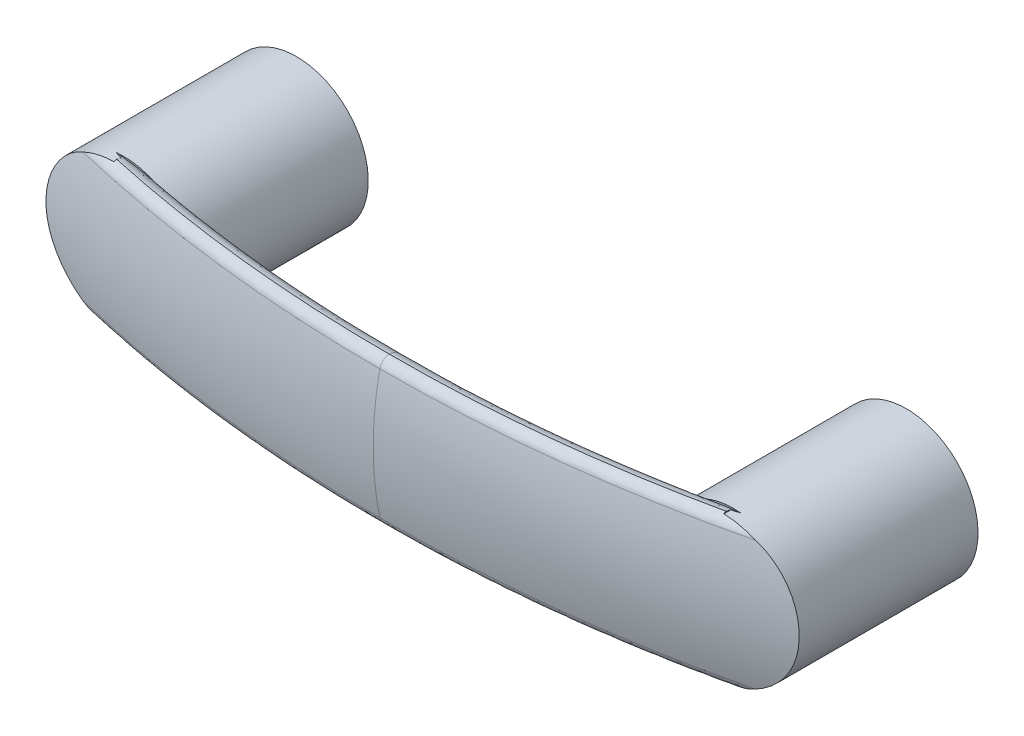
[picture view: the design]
ISO-10303-21;
HEADER;
FILE_DESCRIPTION(('STEP AP214'),'2;1');
FILE_NAME('part.step','',(''),(''),'','','');
FILE_SCHEMA(('AUTOMOTIVE_DESIGN { 1 0 10303 214 1 1 1 1 }'));
ENDSEC;
DATA;
#1=APPLICATION_CONTEXT('core data for automotive mechanical design processes');
#2=APPLICATION_PROTOCOL_DEFINITION('international standard','automotive_design',2000,#1);
#3=PRODUCT_CONTEXT('',#1,'mechanical');
#4=PRODUCT('Part','Part','',(#3));
#5=PRODUCT_RELATED_PRODUCT_CATEGORY('part','',(#4));
#6=PRODUCT_DEFINITION_FORMATION('','',#4);
#7=PRODUCT_DEFINITION_CONTEXT('part definition',#1,'design');
#8=PRODUCT_DEFINITION('design','',#6,#7);
#9=PRODUCT_DEFINITION_SHAPE('','',#8);
#10=(LENGTH_UNIT() NAMED_UNIT(*) SI_UNIT(.MILLI.,.METRE.));
#11=(NAMED_UNIT(*) PLANE_ANGLE_UNIT() SI_UNIT($,.RADIAN.));
#12=(NAMED_UNIT(*) SI_UNIT($,.STERADIAN.) SOLID_ANGLE_UNIT());
#13=UNCERTAINTY_MEASURE_WITH_UNIT(LENGTH_MEASURE(1.E-05),#10,'distance_accuracy_value','');
#14=(GEOMETRIC_REPRESENTATION_CONTEXT(3) GLOBAL_UNCERTAINTY_ASSIGNED_CONTEXT((#13)) GLOBAL_UNIT_ASSIGNED_CONTEXT((#10,
#11,#12)) REPRESENTATION_CONTEXT('',''));
#15=CARTESIAN_POINT('',(0.,0.,0.));
#16=DIRECTION('',(0.,0.,1.));
#17=DIRECTION('',(1.,0.,0.));
#18=AXIS2_PLACEMENT_3D('',#15,#16,#17);
#19=CARTESIAN_POINT('',(125.191834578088,0.,31.4954607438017));
#20=DIRECTION('',(0.940144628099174,0.,-0.340775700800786));
#21=DIRECTION('',(0.,1.,0.));
#22=AXIS2_PLACEMENT_3D('',#19,#20,#21);
#23=CIRCLE('',#22,17.6);
#24=CARTESIAN_POINT('',(47.2434292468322,0.,-184.999446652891));
#25=DIRECTION('',(0.,-1.,0.));
#26=AXIS1_PLACEMENT('',#24,#25);
#27=SURFACE_OF_REVOLUTION('',#23,#26);
#28=CARTESIAN_POINT('',(47.2434292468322,9.54893617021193,-184.999446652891));
#29=DIRECTION('',(0.,-1.,0.));
#30=DIRECTION('',(1.,0.,0.));
#31=AXIS2_PLACEMENT_3D('',#28,#29,#30);
#32=CIRCLE('',#31,215.315634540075);
#33=CARTESIAN_POINT('',(88.0394306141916,9.54893617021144,26.4160417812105));
#34=VERTEX_POINT('',#33);
#35=CARTESIAN_POINT('',(46.75,9.54893617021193,30.3156225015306));
#36=VERTEX_POINT('',#35);
#37=EDGE_CURVE('E344',#34,#36,#32,.T.);
#38=ORIENTED_EDGE('',*,*,#37,.F.);
#39=CARTESIAN_POINT('',(88.0394306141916,9.54893617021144,26.4160417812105));
#40=CARTESIAN_POINT('',(87.7659781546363,9.39256816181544,26.3659144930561));
#41=CARTESIAN_POINT('',(87.5001444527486,9.22495922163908,26.3100965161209));
#42=CARTESIAN_POINT('',(86.9850934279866,8.86870622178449,26.1903628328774));
#43=CARTESIAN_POINT('',(86.7358674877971,8.68007320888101,26.1264513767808));
#44=CARTESIAN_POINT('',(86.2549146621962,8.28288099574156,25.9936978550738));
#45=CARTESIAN_POINT('',(86.0232030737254,8.07430472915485,25.9248515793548));
#46=CARTESIAN_POINT('',(85.5785573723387,7.63856320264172,25.7851894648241));
#47=CARTESIAN_POINT('',(85.3656258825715,7.41139535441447,25.7143733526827));
#48=CARTESIAN_POINT('',(84.9598901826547,6.93996644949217,25.5735382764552));
#49=CARTESIAN_POINT('',(84.767064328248,6.69572425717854,25.503518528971));
#50=CARTESIAN_POINT('',(84.4024240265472,6.19120146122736,25.3666345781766));
#51=CARTESIAN_POINT('',(84.2306086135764,5.93092159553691,25.2997702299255));
#52=CARTESIAN_POINT('',(83.9092638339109,5.3958426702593,25.1714425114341));
#53=CARTESIAN_POINT('',(83.7597239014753,5.12105057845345,25.1099765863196));
#54=CARTESIAN_POINT('',(83.4840804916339,4.55845019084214,24.9944101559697));
#55=CARTESIAN_POINT('',(83.3579767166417,4.2706420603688,24.9403095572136));
#56=CARTESIAN_POINT('',(83.1312382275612,3.68597163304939,24.8415872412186));
#57=CARTESIAN_POINT('',(83.0304297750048,3.38918772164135,24.7969012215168));
#58=CARTESIAN_POINT('',(82.8542371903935,2.78679081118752,24.7179869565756));
#59=CARTESIAN_POINT('',(82.7788530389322,2.48117781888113,24.6837587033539));
#60=CARTESIAN_POINT('',(82.6544576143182,1.86369394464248,24.6269116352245));
#61=CARTESIAN_POINT('',(82.6054351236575,1.55182578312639,24.6042878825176));
#62=CARTESIAN_POINT('',(82.534364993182,0.92439332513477,24.5713971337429));
#63=CARTESIAN_POINT('',(82.5123150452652,0.608829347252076,24.561129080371));
#64=CARTESIAN_POINT('',(82.4962294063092,0.00490154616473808,24.553642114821));
#65=CARTESIAN_POINT('',(82.4998806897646,-0.283390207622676,24.5553457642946));
#66=CARTESIAN_POINT('',(82.5297753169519,-0.858531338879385,24.569245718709));
#67=CARTESIAN_POINT('',(82.5560171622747,-1.14538081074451,24.5814413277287));
#68=CARTESIAN_POINT('',(82.6307875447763,-1.71547764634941,24.6159755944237));
#69=CARTESIAN_POINT('',(82.6793119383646,-1.99872566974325,24.6383123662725));
#70=CARTESIAN_POINT('',(82.7981215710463,-2.5596876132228,24.6925021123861));
#71=CARTESIAN_POINT('',(82.8684071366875,-2.83740145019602,24.7243552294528));
#72=CARTESIAN_POINT('',(83.0287380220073,-3.38108213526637,24.7961202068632));
#73=CARTESIAN_POINT('',(83.1184496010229,-3.64716578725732,24.8358951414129));
#74=CARTESIAN_POINT('',(83.3174624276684,-4.17065270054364,24.9227645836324));
#75=CARTESIAN_POINT('',(83.426763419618,-4.42805607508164,24.9698589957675));
#76=CARTESIAN_POINT('',(83.6641855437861,-4.9330168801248,25.0701879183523));
#77=CARTESIAN_POINT('',(83.7923206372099,-5.18056683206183,25.1234269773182));
#78=CARTESIAN_POINT('',(84.0664699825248,-5.66443678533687,25.2346446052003));
#79=CARTESIAN_POINT('',(84.2124846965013,-5.90075649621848,25.2926232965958));
#80=CARTESIAN_POINT('',(84.5336729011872,-6.37921546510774,25.4164948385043));
#81=CARTESIAN_POINT('',(84.7102357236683,-6.62035455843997,25.482651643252));
#82=CARTESIAN_POINT('',(85.0821485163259,-7.08723311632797,25.6166659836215));
#83=CARTESIAN_POINT('',(85.2775016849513,-7.31296994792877,25.6845238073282));
#84=CARTESIAN_POINT('',(85.6857189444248,-7.74763122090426,25.8195792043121));
#85=CARTESIAN_POINT('',(85.8985594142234,-7.95657761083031,25.8867775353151));
#86=CARTESIAN_POINT('',(86.3409422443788,-8.35684289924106,26.0181186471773));
#87=CARTESIAN_POINT('',(86.5704771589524,-8.54816957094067,26.0822627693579));
#88=CARTESIAN_POINT('',(87.0030334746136,-8.87974544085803,26.1939239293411));
#89=CARTESIAN_POINT('',(87.20349851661,-9.02302345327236,26.2423678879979));
#90=CARTESIAN_POINT('',(87.6142270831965,-9.29615203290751,26.3337292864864));
#91=CARTESIAN_POINT('',(87.8244791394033,-9.42601776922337,26.3766529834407));
#92=CARTESIAN_POINT('',(88.0394306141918,-9.54893617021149,26.4160417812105));
#93=B_SPLINE_CURVE_WITH_KNOTS('',3,(#39,#40,#41,#42,#43,#44,#45,#46,#47,#48,#49,#50,#51,#52,#53,
#54,#55,#56,#57,#58,#59,#60,#61,#62,#63,#64,#65,#66,#67,#68,#69,#70,#71,#72,#73,#74,#75,#76,#77,
#78,#79,#80,#81,#82,#83,#84,#85,#86,#87,#88,#89,#90,#91,#92),.UNSPECIFIED.,.F.,.F.,(4,2,2,2,2,2,
2,2,2,2,2,2,2,2,2,2,2,2,2,2,2,2,2,2,2,2,4),(0.,0.956383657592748,1.9122671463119,
2.86897607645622,3.8258184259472,4.78161983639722,5.73737730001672,6.69267997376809,
7.64797051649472,8.59650814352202,9.54504504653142,10.4931780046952,11.4412298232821,
12.3051248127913,13.1689625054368,14.0326396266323,14.8963297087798,15.7462167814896,
16.5960927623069,17.4466019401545,18.297133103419,19.2144510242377,20.1319253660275,
21.0481801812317,21.9640288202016,22.7168036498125,23.4687175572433),.UNSPECIFIED.);
#94=CARTESIAN_POINT('',(88.0394306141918,-9.54893617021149,26.4160417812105));
#95=VERTEX_POINT('',#94);
#96=EDGE_CURVE('E634',#34,#95,#93,.T.);
#97=ORIENTED_EDGE('',*,*,#96,.T.);
#98=CARTESIAN_POINT('',(47.2434292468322,-9.54893617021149,-184.999446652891));
#99=DIRECTION('',(0.,-1.,0.));
#100=DIRECTION('',(1.,0.,0.));
#101=AXIS2_PLACEMENT_3D('',#98,#99,#100);
#102=CIRCLE('',#101,215.315634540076);
#103=CARTESIAN_POINT('',(46.75,-9.54893617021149,30.3156225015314));
#104=VERTEX_POINT('',#103);
#105=EDGE_CURVE('E342',#95,#104,#102,.T.);
#106=ORIENTED_EDGE('',*,*,#105,.T.);
#107=CARTESIAN_POINT('',(46.75,0.,45.1));
#108=DIRECTION('',(1.,0.,0.));
#109=DIRECTION('',(0.,1.,0.));
#110=AXIS2_PLACEMENT_3D('',#107,#108,#109);
#111=CIRCLE('',#110,17.6);
#112=EDGE_CURVE('E563',#104,#36,#111,.T.);
#113=ORIENTED_EDGE('',*,*,#112,.T.);
#114=EDGE_LOOP('',(#38,#97,#106,#113));
#115=FACE_BOUND('',#114,.T.);
#116=ADVANCED_FACE('F14',(#115),#27,.T.);
#117=CARTESIAN_POINT('',(0.,0.,0.));
#118=DIRECTION('',(0.,0.,1.));
#119=DIRECTION('',(0.,-1.,0.));
#120=AXIS2_PLACEMENT_3D('',#117,#118,#119);
#121=PLANE('',#120);
#122=CARTESIAN_POINT('',(0.,0.,0.));
#123=DIRECTION('',(0.,0.,1.));
#124=DIRECTION('',(0.,-1.,0.));
#125=AXIS2_PLACEMENT_3D('',#122,#123,#124);
#126=CIRCLE('',#125,11.);
#127=CARTESIAN_POINT('',(0.,-11.,0.));
#128=VERTEX_POINT('',#127);
#129=EDGE_CURVE('E722',#128,#128,#126,.T.);
#130=ORIENTED_EDGE('',*,*,#129,.F.);
#131=EDGE_LOOP('',(#130));
#132=FACE_BOUND('',#131,.T.);
#133=CARTESIAN_POINT('',(0.,0.,0.));
#134=DIRECTION('',(0.,0.,1.));
#135=DIRECTION('',(0.,-1.,0.));
#136=AXIS2_PLACEMENT_3D('',#133,#134,#135);
#137=CIRCLE('',#136,3.);
#138=CARTESIAN_POINT('',(0.,-3.,0.));
#139=VERTEX_POINT('',#138);
#140=EDGE_CURVE('E355',#139,#139,#137,.T.);
#141=ORIENTED_EDGE('',*,*,#140,.T.);
#142=EDGE_LOOP('',(#141));
#143=FACE_BOUND('',#142,.T.);
#144=ADVANCED_FACE('F535',(#132,#143),#121,.F.);
#145=CARTESIAN_POINT('',(-27.4898489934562,-8.47425322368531,19.9028672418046));
#146=DIRECTION('',(0.940144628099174,0.,0.340775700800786));
#147=DIRECTION('',(0.,1.,0.));
#148=AXIS2_PLACEMENT_3D('',#145,#146,#147);
#149=CIRCLE('',#148,2.67875466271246);
#150=CARTESIAN_POINT('',(46.2565707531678,0.,-184.999446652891));
#151=DIRECTION('',(0.,1.,0.));
#152=AXIS1_PLACEMENT('',#150,#151);
#153=SURFACE_OF_REVOLUTION('',#149,#152);
#154=CARTESIAN_POINT('',(46.2565707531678,-11.1437941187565,-184.999446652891));
#155=DIRECTION('',(0.,1.,0.));
#156=DIRECTION('',(-1.,0.,0.));
#157=AXIS2_PLACEMENT_3D('',#154,#155,#156);
#158=CIRCLE('',#157,217.547370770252);
#159=CARTESIAN_POINT('',(0.,-11.1437941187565,27.5733366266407));
#160=VERTEX_POINT('',#159);
#161=CARTESIAN_POINT('',(46.75,-11.1437941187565,32.5473645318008));
#162=VERTEX_POINT('',#161);
#163=EDGE_CURVE('E492',#160,#162,#158,.T.);
#164=ORIENTED_EDGE('',*,*,#163,.F.);
#165=CARTESIAN_POINT('',(0.,-11.1437941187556,27.5733366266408));
#166=CARTESIAN_POINT('',(0.,-11.1343057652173,27.4564772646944));
#167=CARTESIAN_POINT('',(0.,-11.1174827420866,27.3403480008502));
#168=CARTESIAN_POINT('',(0.,-11.0854857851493,27.1876211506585));
#169=CARTESIAN_POINT('',(0.,-11.0767014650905,27.1496593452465));
#170=CARTESIAN_POINT('',(0.,-11.0575359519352,27.074068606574));
#171=CARTESIAN_POINT('',(0.,-11.0471519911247,27.0364403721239));
#172=CARTESIAN_POINT('',(0.,-11.0247761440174,26.9615212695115));
#173=CARTESIAN_POINT('',(0.,-11.0127787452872,26.9242320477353));
#174=CARTESIAN_POINT('',(0.,-11.0000000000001,26.8872131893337));
#175=B_SPLINE_CURVE_WITH_KNOTS('',3,(#165,#166,#167,#168,#169,#170,#171,#172,#173,#174),
.UNSPECIFIED.,.F.,.F.,(4,2,2,2,4),(0.,0.351207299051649,0.46807188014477,0.585140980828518,
0.702620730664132),.UNSPECIFIED.);
#176=CARTESIAN_POINT('',(0.,-11.,26.8872131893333));
#177=VERTEX_POINT('',#176);
#178=EDGE_CURVE('E469',#160,#177,#175,.T.);
#179=ORIENTED_EDGE('',*,*,#178,.T.);
#180=CARTESIAN_POINT('',(0.,-11.,26.8872131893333));
#181=CARTESIAN_POINT('',(-0.0707909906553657,-11.0000010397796,26.8717864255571));
#182=CARTESIAN_POINT('',(-0.141130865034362,-10.9993167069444,26.8543859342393));
#183=CARTESIAN_POINT('',(-0.280472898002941,-10.9966431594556,26.8161161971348));
#184=CARTESIAN_POINT('',(-0.34947987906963,-10.9946602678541,26.7952641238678));
#185=CARTESIAN_POINT('',(-0.486250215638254,-10.9894602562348,26.7504645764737));
#186=CARTESIAN_POINT('',(-0.554016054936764,-10.9862459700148,26.7265242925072));
#187=CARTESIAN_POINT('',(-0.688436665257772,-10.9786421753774,26.6759910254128));
#188=CARTESIAN_POINT('',(-0.755092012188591,-10.9742532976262,26.6493994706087));
#189=CARTESIAN_POINT('',(-0.886809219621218,-10.9643920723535,26.594243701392));
#190=CARTESIAN_POINT('',(-0.951879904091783,-10.9589294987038,26.565698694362));
#191=CARTESIAN_POINT('',(-1.0811703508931,-10.9469306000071,26.5068048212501));
#192=CARTESIAN_POINT('',(-1.14538924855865,-10.9403932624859,26.4764542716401));
#193=CARTESIAN_POINT('',(-1.2730686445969,-10.9262722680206,26.4142934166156));
#194=CARTESIAN_POINT('',(-1.33652841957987,-10.9186876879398,26.3824818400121));
#195=CARTESIAN_POINT('',(-1.46275845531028,-10.9024945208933,26.3176990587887));
#196=CARTESIAN_POINT('',(-1.52552835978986,-10.8938854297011,26.2847272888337));
#197=CARTESIAN_POINT('',(-1.72299672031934,-10.8650777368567,26.1790708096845));
#198=CARTESIAN_POINT('',(-1.8565508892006,-10.8430331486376,26.1047449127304));
#199=CARTESIAN_POINT('',(-2.12146647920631,-10.7943275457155,25.9537877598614));
#200=CARTESIAN_POINT('',(-2.25282799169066,-10.767666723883,25.877156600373));
#201=CARTESIAN_POINT('',(-2.51390523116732,-10.7097226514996,25.7228198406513));
#202=CARTESIAN_POINT('',(-2.64362080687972,-10.6784389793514,25.6451141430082));
#203=CARTESIAN_POINT('',(-2.90174277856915,-10.6112050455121,25.4895610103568));
#204=CARTESIAN_POINT('',(-3.03014922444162,-10.5752549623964,25.4117135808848));
#205=CARTESIAN_POINT('',(-3.28587123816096,-10.4986123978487,25.2566196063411));
#206=CARTESIAN_POINT('',(-3.41318701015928,-10.4579208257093,25.1793729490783));
#207=CARTESIAN_POINT('',(-3.67011932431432,-10.3705880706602,25.0241594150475));
#208=CARTESIAN_POINT('',(-3.79971252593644,-10.3238223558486,24.946223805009));
#209=CARTESIAN_POINT('',(-4.05803006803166,-10.2250433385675,24.7922849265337));
#210=CARTESIAN_POINT('',(-4.18675449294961,-10.1730305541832,24.7162814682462));
#211=CARTESIAN_POINT('',(-4.44342425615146,-10.0635703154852,24.5668343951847));
#212=CARTESIAN_POINT('',(-4.57136941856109,-10.0061216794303,24.4933913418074));
#213=CARTESIAN_POINT('',(-4.82656913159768,-9.88555374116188,24.3497121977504));
#214=CARTESIAN_POINT('',(-4.95382299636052,-9.82242962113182,24.2794789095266));
#215=CARTESIAN_POINT('',(-5.20772652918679,-9.69020503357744,24.1429695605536));
#216=CARTESIAN_POINT('',(-5.33437453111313,-9.621093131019,24.0767014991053));
#217=CARTESIAN_POINT('',(-5.4605693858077,-9.54893617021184,24.0128972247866));
#218=B_SPLINE_CURVE_WITH_KNOTS('',3,(#180,#181,#182,#183,#184,#185,#186,#187,#188,#189,#190,
#191,#192,#193,#194,#195,#196,#197,#198,#199,#200,#201,#202,#203,#204,#205,#206,#207,#208,#209,
#210,#211,#212,#213,#214,#215,#216,#217),.UNSPECIFIED.,.F.,.F.,(4,2,2,2,2,2,2,2,2,2,2,2,2,2,2,2,
2,2,4),(0.,0.217296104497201,0.433541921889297,0.649293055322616,0.864928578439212,
1.07868519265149,1.29264434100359,1.50679331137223,1.72104811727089,2.18418173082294,
2.64729599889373,3.11045252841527,3.57359133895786,4.03664147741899,4.51141309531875,
4.9861378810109,5.46096610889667,5.9362012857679,6.41236492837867),.UNSPECIFIED.);
#219=CARTESIAN_POINT('',(-1.094948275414,-10.9453683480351,26.5));
#220=VERTEX_POINT('',#219);
#221=EDGE_CURVE('E421',#177,#220,#218,.T.);
#222=ORIENTED_EDGE('',*,*,#221,.T.);
#223=CARTESIAN_POINT('',(5.89809527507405,-9.54893617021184,26.5));
#224=CARTESIAN_POINT('',(5.85335939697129,-9.56807767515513,26.5));
#225=CARTESIAN_POINT('',(5.80841977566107,-9.58673543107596,26.5));
#226=CARTESIAN_POINT('',(5.71819153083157,-9.62317676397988,26.5));
#227=CARTESIAN_POINT('',(5.67290293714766,-9.64096041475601,26.5));
#228=CARTESIAN_POINT('',(5.53662401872,-9.69313186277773,26.5));
#229=CARTESIAN_POINT('',(5.44518698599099,-9.72635434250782,26.5));
#230=CARTESIAN_POINT('',(5.26174364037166,-9.79012691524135,26.5));
#231=CARTESIAN_POINT('',(5.1697403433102,-9.82068575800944,26.5));
#232=CARTESIAN_POINT('',(4.98503806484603,-9.87964899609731,26.5));
#233=CARTESIAN_POINT('',(4.89233900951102,-9.90805315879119,26.5));
#234=CARTESIAN_POINT('',(4.61362266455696,-9.99043080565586,26.5));
#235=CARTESIAN_POINT('',(4.42678651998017,-10.0416372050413,26.5));
#236=CARTESIAN_POINT('',(4.05166982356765,-10.1382884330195,26.5));
#237=CARTESIAN_POINT('',(3.86338939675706,-10.1837337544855,26.5));
#238=CARTESIAN_POINT('',(3.48678691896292,-10.2696575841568,26.5));
#239=CARTESIAN_POINT('',(3.29847072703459,-10.3101618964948,26.5));
#240=CARTESIAN_POINT('',(2.92092039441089,-10.387209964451,26.5));
#241=CARTESIAN_POINT('',(2.7316857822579,-10.4237513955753,26.5));
#242=CARTESIAN_POINT('',(2.35250104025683,-10.4933553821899,26.5));
#243=CARTESIAN_POINT('',(2.16255065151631,-10.5264165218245,26.5));
#244=CARTESIAN_POINT('',(1.78211504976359,-10.5894080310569,26.5));
#245=CARTESIAN_POINT('',(1.59162978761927,-10.6193381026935,26.5));
#246=CARTESIAN_POINT('',(1.16928207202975,-10.6824552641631,26.5));
#247=CARTESIAN_POINT('',(0.937317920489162,-10.7149616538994,26.5));
#248=CARTESIAN_POINT('',(0.472949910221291,-10.7760965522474,26.5));
#249=CARTESIAN_POINT('',(0.240546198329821,-10.8047261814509,26.5));
#250=CARTESIAN_POINT('',(-0.224641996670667,-10.8583639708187,26.5));
#251=CARTESIAN_POINT('',(-0.457426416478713,-10.8833726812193,26.5));
#252=CARTESIAN_POINT('',(-0.92332466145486,-10.9299465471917,26.5));
#253=CARTESIAN_POINT('',(-1.15643846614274,-10.9515119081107,26.5));
#254=CARTESIAN_POINT('',(-1.62446194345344,-10.9914452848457,26.5));
#255=CARTESIAN_POINT('',(-1.85937345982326,-11.0097916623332,26.5));
#256=CARTESIAN_POINT('',(-2.32944842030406,-11.0431842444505,26.5));
#257=CARTESIAN_POINT('',(-2.56461188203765,-11.0582302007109,26.5));
#258=CARTESIAN_POINT('',(-3.03515232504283,-11.0850508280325,26.5));
#259=CARTESIAN_POINT('',(-3.27052932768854,-11.0968251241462,26.5));
#260=CARTESIAN_POINT('',(-3.74146064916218,-11.1170841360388,26.5));
#261=CARTESIAN_POINT('',(-3.97701498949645,-11.1255683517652,26.5));
#262=CARTESIAN_POINT('',(-4.2126175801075,-11.1323977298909,26.5));
#263=B_SPLINE_CURVE_WITH_KNOTS('',3,(#223,#224,#225,#226,#227,#228,#229,#230,#231,#232,#233,
#234,#235,#236,#237,#238,#239,#240,#241,#242,#243,#244,#245,#246,#247,#248,#249,#250,#251,#252,
#253,#254,#255,#256,#257,#258,#259,#260,#261,#262),.UNSPECIFIED.,.F.,.F.,(4,2,2,2,2,2,2,2,2,2,2,
2,2,2,2,2,2,2,2,4),(0.,0.145969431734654,0.291926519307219,0.583731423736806,0.874538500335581,
1.16537692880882,1.74642171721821,2.32741676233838,2.90523435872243,3.48338907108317,
4.06177808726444,4.64022209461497,5.34287747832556,6.04532932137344,6.74767430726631,
7.44997739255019,8.15683422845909,8.86374423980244,9.57073523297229,10.2778336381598),.UNSPECIFIED.);
#264=CARTESIAN_POINT('',(4.59466619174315,-9.99445058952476,26.5));
#265=VERTEX_POINT('',#264);
#266=EDGE_CURVE('E539',#265,#220,#263,.T.);
#267=ORIENTED_EDGE('',*,*,#266,.F.);
#268=CARTESIAN_POINT('',(4.5946661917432,-9.99445058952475,26.5));
#269=CARTESIAN_POINT('',(4.64373104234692,-9.97189444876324,26.4938196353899));
#270=CARTESIAN_POINT('',(4.69265247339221,-9.94896650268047,26.4878544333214));
#271=CARTESIAN_POINT('',(4.7901662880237,-9.90238479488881,26.4763949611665));
#272=CARTESIAN_POINT('',(4.83875885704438,-9.87873149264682,26.4709004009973));
#273=CARTESIAN_POINT('',(4.93561792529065,-9.83069667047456,26.4604167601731));
#274=CARTESIAN_POINT('',(4.98388452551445,-9.80631539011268,26.4554275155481));
#275=CARTESIAN_POINT('',(5.08009557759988,-9.75682097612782,26.4459897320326));
#276=CARTESIAN_POINT('',(5.12804002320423,-9.7317078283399,26.4415412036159));
#277=CARTESIAN_POINT('',(5.22360672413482,-9.68074718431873,26.433221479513));
#278=CARTESIAN_POINT('',(5.27122887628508,-9.65489946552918,26.4293504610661));
#279=CARTESIAN_POINT('',(5.36615185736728,-9.60246616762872,26.4222237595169));
#280=CARTESIAN_POINT('',(5.41345245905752,-9.57588012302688,26.4189684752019));
#281=CARTESIAN_POINT('',(5.46056938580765,-9.54893617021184,26.4160417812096));
#282=B_SPLINE_CURVE_WITH_KNOTS('',3,(#268,#269,#270,#271,#272,#273,#274,#275,#276,#277,#278,
#279,#280,#281),.UNSPECIFIED.,.F.,.F.,(4,2,2,2,2,2,4),(0.,0.163060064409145,0.326018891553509,
0.488924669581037,0.651833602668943,0.814792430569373,0.977856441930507),.UNSPECIFIED.);
#283=CARTESIAN_POINT('',(5.46056938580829,-9.54893617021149,26.4160417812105));
#284=VERTEX_POINT('',#283);
#285=EDGE_CURVE('E554',#265,#284,#282,.T.);
#286=ORIENTED_EDGE('',*,*,#285,.T.);
#287=CARTESIAN_POINT('',(46.2565707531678,-9.54893617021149,-184.999446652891));
#288=DIRECTION('',(0.,1.,0.));
#289=DIRECTION('',(-1.,0.,0.));
#290=AXIS2_PLACEMENT_3D('',#287,#288,#289);
#291=CIRCLE('',#290,215.315634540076);
#292=EDGE_CURVE('E508',#284,#104,#291,.T.);
#293=ORIENTED_EDGE('',*,*,#292,.T.);
#294=CARTESIAN_POINT('',(46.75,-8.47425322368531,32.7693509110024));
#295=DIRECTION('',(1.,0.,0.));
#296=DIRECTION('',(0.,1.,0.));
#297=AXIS2_PLACEMENT_3D('',#294,#295,#296);
#298=CIRCLE('',#297,2.67875466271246);
#299=EDGE_CURVE('E560',#162,#104,#298,.T.);
#300=ORIENTED_EDGE('',*,*,#299,.F.);
#301=EDGE_LOOP('',(#164,#179,#222,#267,#286,#293,#300));
#302=FACE_BOUND('',#301,.T.);
#303=ADVANCED_FACE('F481',(#302),#153,.F.);
#304=CARTESIAN_POINT('',(-27.4898489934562,8.47425322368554,19.9028672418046));
#305=DIRECTION('',(0.940144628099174,0.,0.340775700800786));
#306=DIRECTION('',(0.,1.,0.));
#307=AXIS2_PLACEMENT_3D('',#304,#305,#306);
#308=CIRCLE('',#307,2.67875466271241);
#309=CARTESIAN_POINT('',(46.2565707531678,0.,-184.999446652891));
#310=DIRECTION('',(0.,1.,0.));
#311=AXIS1_PLACEMENT('',#309,#310);
#312=SURFACE_OF_REVOLUTION('',#308,#311);
#313=CARTESIAN_POINT('',(-4.6830267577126,11.1437941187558,26.5));
#314=CARTESIAN_POINT('',(-4.45868645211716,11.1394208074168,26.5));
#315=CARTESIAN_POINT('',(-4.23437640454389,11.1335242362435,26.5));
#316=CARTESIAN_POINT('',(-3.78591677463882,11.1187238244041,26.5));
#317=CARTESIAN_POINT('',(-3.56176716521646,11.1098208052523,26.5));
#318=CARTESIAN_POINT('',(-3.11364753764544,11.0890462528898,26.5));
#319=CARTESIAN_POINT('',(-2.88967749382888,11.0771752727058,26.5));
#320=CARTESIAN_POINT('',(-2.44193726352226,11.0504657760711,26.5));
#321=CARTESIAN_POINT('',(-2.21816705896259,11.0356275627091,26.5));
#322=CARTESIAN_POINT('',(-1.77213393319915,11.0030483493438,26.5));
#323=CARTESIAN_POINT('',(-1.54986975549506,10.9853245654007,26.5));
#324=CARTESIAN_POINT('',(-1.1055836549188,10.9468500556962,26.5));
#325=CARTESIAN_POINT('',(-0.883561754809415,10.9260990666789,26.5000000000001));
#326=CARTESIAN_POINT('',(-0.439789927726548,10.8814645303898,26.4999999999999));
#327=CARTESIAN_POINT('',(-0.218040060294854,10.85758038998,26.4999999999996));
#328=CARTESIAN_POINT('',(0.225153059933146,10.8065229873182,26.5000000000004));
#329=CARTESIAN_POINT('',(0.446596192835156,10.779348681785,26.5000000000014));
#330=CARTESIAN_POINT('',(0.889429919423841,10.7214502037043,26.5000000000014));
#331=CARTESIAN_POINT('',(1.11081968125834,10.6907196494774,26.5000000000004));
#332=CARTESIAN_POINT('',(1.55302248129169,10.62545238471,26.4999999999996));
#333=CARTESIAN_POINT('',(1.77383556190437,10.5909159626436,26.4999999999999));
#334=CARTESIAN_POINT('',(2.21466775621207,10.5176357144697,26.5000000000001));
#335=CARTESIAN_POINT('',(2.43468717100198,10.4788937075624,26.5));
#336=CARTESIAN_POINT('',(2.87368998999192,10.396634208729,26.5));
#337=CARTESIAN_POINT('',(3.09267397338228,10.3531198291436,26.5));
#338=CARTESIAN_POINT('',(3.53077464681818,10.2601703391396,26.5));
#339=CARTESIAN_POINT('',(3.74988410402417,10.2107009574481,26.5));
#340=CARTESIAN_POINT('',(4.1864536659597,10.1047714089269,26.5));
#341=CARTESIAN_POINT('',(4.40391365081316,10.0483107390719,26.5));
#342=CARTESIAN_POINT('',(4.72830269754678,9.95675773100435,26.5));
#343=CARTESIAN_POINT('',(4.83619499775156,9.9250757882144,26.5));
#344=CARTESIAN_POINT('',(5.05114018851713,9.85902106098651,26.5));
#345=CARTESIAN_POINT('',(5.15819319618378,9.82464865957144,26.5));
#346=CARTESIAN_POINT('',(5.37163956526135,9.75252985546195,26.5));
#347=CARTESIAN_POINT('',(5.47802864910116,9.7147706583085,26.5));
#348=CARTESIAN_POINT('',(5.63649496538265,9.6550891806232,26.5));
#349=CARTESIAN_POINT('',(5.68914355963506,9.63468289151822,26.5));
#350=CARTESIAN_POINT('',(5.793984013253,9.59271290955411,26.5));
#351=CARTESIAN_POINT('',(5.84617581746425,9.57114907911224,26.5));
#352=CARTESIAN_POINT('',(5.89809527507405,9.54893617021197,26.5));
#353=B_SPLINE_CURVE_WITH_KNOTS('',3,(#313,#314,#315,#316,#317,#318,#319,#320,#321,#322,#323,
#324,#325,#326,#327,#328,#329,#330,#331,#332,#333,#334,#335,#336,#337,#338,#339,#340,#341,#342,
#343,#344,#345,#346,#347,#348,#349,#350,#351,#352),.UNSPECIFIED.,.F.,.F.,(4,2,2,2,2,2,2,2,2,2,2,
2,2,2,2,2,2,2,2,4),(0.,0.673142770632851,1.3461017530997,2.01893543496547,2.69170042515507,
3.36058947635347,4.02953673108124,4.6986108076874,5.36789759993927,6.03840461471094,
6.70886084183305,7.37902819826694,8.04876106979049,8.72255123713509,9.39638991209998,
9.73370530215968,10.0709727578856,10.4095727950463,10.5789554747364,10.7483583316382),.UNSPECIFIED.);
#354=CARTESIAN_POINT('',(-1.0949482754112,10.9453683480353,26.5));
#355=VERTEX_POINT('',#354);
#356=CARTESIAN_POINT('',(4.5946661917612,9.99445058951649,26.5));
#357=VERTEX_POINT('',#356);
#358=EDGE_CURVE('E511',#355,#357,#353,.T.);
#359=ORIENTED_EDGE('',*,*,#358,.F.);
#360=CARTESIAN_POINT('',(-5.4605693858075,9.54893617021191,24.0128972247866));
#361=CARTESIAN_POINT('',(-5.35158831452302,9.61125288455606,24.0679927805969));
#362=CARTESIAN_POINT('',(-5.24226574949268,9.67129756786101,24.1249341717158));
#363=CARTESIAN_POINT('',(-5.02322692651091,9.78685393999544,24.2418321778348));
#364=CARTESIAN_POINT('',(-4.91351214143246,9.84237568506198,24.3017815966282));
#365=CARTESIAN_POINT('',(-4.6936195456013,9.94911290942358,24.4241981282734));
#366=CARTESIAN_POINT('',(-4.58344250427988,10.0003337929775,24.4866619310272));
#367=CARTESIAN_POINT('',(-4.3625558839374,10.0986490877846,24.613680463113));
#368=CARTESIAN_POINT('',(-4.25184665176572,10.1457458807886,24.678233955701));
#369=CARTESIAN_POINT('',(-4.02982812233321,10.2359582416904,24.809028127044));
#370=CARTESIAN_POINT('',(-3.91851889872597,10.2790742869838,24.8752686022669));
#371=CARTESIAN_POINT('',(-3.69736365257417,10.3606528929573,25.0077619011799));
#372=CARTESIAN_POINT('',(-3.5875299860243,10.3991882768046,25.0739906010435));
#373=CARTESIAN_POINT('',(-3.36711937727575,10.4726312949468,25.2073144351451));
#374=CARTESIAN_POINT('',(-3.25654217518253,10.5075375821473,25.2744098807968));
#375=CARTESIAN_POINT('',(-3.0345313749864,10.573790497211,25.4090531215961));
#376=CARTESIAN_POINT('',(-2.92309743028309,10.6051355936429,25.4766010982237));
#377=CARTESIAN_POINT('',(-2.69921796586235,10.6643159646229,25.6116735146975));
#378=CARTESIAN_POINT('',(-2.5867720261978,10.692149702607,25.6791979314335));
#379=CARTESIAN_POINT('',(-2.36064556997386,10.744339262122,25.8136499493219));
#380=CARTESIAN_POINT('',(-2.24696450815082,10.7686934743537,25.8805772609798));
#381=CARTESIAN_POINT('',(-2.04937093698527,10.8077408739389,25.9949552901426));
#382=CARTESIAN_POINT('',(-1.96580929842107,10.8232558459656,26.0427323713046));
#383=CARTESIAN_POINT('',(-1.79778619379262,10.8524298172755,26.1371541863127));
#384=CARTESIAN_POINT('',(-1.71332524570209,10.866089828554,26.1837995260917));
#385=CARTESIAN_POINT('',(-1.54336623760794,10.8915286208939,26.2754555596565));
#386=CARTESIAN_POINT('',(-1.45786950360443,10.9033095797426,26.3204680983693));
#387=CARTESIAN_POINT('',(-1.2856358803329,10.9249560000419,26.4082404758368));
#388=CARTESIAN_POINT('',(-1.19890092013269,10.9348241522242,26.4510034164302));
#389=CARTESIAN_POINT('',(-1.02285423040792,10.9527020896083,26.5340177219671));
#390=CARTESIAN_POINT('',(-0.933524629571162,10.9606901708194,26.5742361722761));
#391=CARTESIAN_POINT('',(-0.75293856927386,10.9745746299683,26.6506498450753));
#392=CARTESIAN_POINT('',(-0.661681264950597,10.9804700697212,26.6868432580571));
#393=CARTESIAN_POINT('',(-0.476837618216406,10.9900505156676,26.7541263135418));
#394=CARTESIAN_POINT('',(-0.383244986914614,10.993728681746,26.7851999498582));
#395=CARTESIAN_POINT('',(-0.241043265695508,10.9974619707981,26.8271246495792));
#396=CARTESIAN_POINT('',(-0.193154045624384,10.9984092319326,26.8403600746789));
#397=CARTESIAN_POINT('',(-0.0969122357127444,10.9996784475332,26.8651070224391));
#398=CARTESIAN_POINT('',(-0.0485595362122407,11.0000002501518,26.8766181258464));
#399=CARTESIAN_POINT('',(0.,10.9999999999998,26.8872131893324));
#400=B_SPLINE_CURVE_WITH_KNOTS('',3,(#360,#361,#362,#363,#364,#365,#366,#367,#368,#369,#370,
#371,#372,#373,#374,#375,#376,#377,#378,#379,#380,#381,#382,#383,#384,#385,#386,#387,#388,#389,
#390,#391,#392,#393,#394,#395,#396,#397,#398,#399),.UNSPECIFIED.,.F.,.F.,(4,2,2,2,2,2,2,2,2,2,2,
2,2,2,2,2,2,2,2,4),(0.,0.411233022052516,0.82152523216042,1.23129392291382,1.64082438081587,
2.05030566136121,2.45201061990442,2.85386415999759,3.25588986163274,3.65809088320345,
4.06047732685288,4.35294815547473,4.64525877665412,4.93722811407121,5.22878371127,
5.52355595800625,5.81846019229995,6.11426958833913,6.26331784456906,6.4124022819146),.UNSPECIFIED.);
#401=CARTESIAN_POINT('',(0.,11.,26.8872131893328));
#402=VERTEX_POINT('',#401);
#403=EDGE_CURVE('E412',#355,#402,#400,.T.);
#404=ORIENTED_EDGE('',*,*,#403,.T.);
#405=CARTESIAN_POINT('',(0.,11.,26.8872131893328));
#406=CARTESIAN_POINT('',(0.,11.0127787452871,26.9242320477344));
#407=CARTESIAN_POINT('',(0.,11.0247761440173,26.9615212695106));
#408=CARTESIAN_POINT('',(0.,11.0471519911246,27.0364403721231));
#409=CARTESIAN_POINT('',(0.,11.0575359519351,27.0740686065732));
#410=CARTESIAN_POINT('',(0.,11.0767014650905,27.1496593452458));
#411=CARTESIAN_POINT('',(0.,11.0854857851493,27.1876211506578));
#412=CARTESIAN_POINT('',(0.,11.1174827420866,27.3403480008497));
#413=CARTESIAN_POINT('',(0.,11.1343057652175,27.456477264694));
#414=CARTESIAN_POINT('',(0.,11.1437941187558,27.5733366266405));
#415=B_SPLINE_CURVE_WITH_KNOTS('',3,(#405,#406,#407,#408,#409,#410,#411,#412,#413,#414),
.UNSPECIFIED.,.F.,.F.,(4,2,2,2,4),(0.,0.117479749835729,0.234548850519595,0.351413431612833,
0.702620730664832),.UNSPECIFIED.);
#416=CARTESIAN_POINT('',(0.,11.1437941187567,27.5733366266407));
#417=VERTEX_POINT('',#416);
#418=EDGE_CURVE('E385',#402,#417,#415,.T.);
#419=ORIENTED_EDGE('',*,*,#418,.T.);
#420=CARTESIAN_POINT('',(46.2565707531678,11.1437941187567,-184.999446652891));
#421=DIRECTION('',(0.,1.,0.));
#422=DIRECTION('',(-1.,0.,0.));
#423=AXIS2_PLACEMENT_3D('',#420,#421,#422);
#424=CIRCLE('',#423,217.547370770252);
#425=CARTESIAN_POINT('',(46.75,11.1437941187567,32.5473645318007));
#426=VERTEX_POINT('',#425);
#427=EDGE_CURVE('E502',#417,#426,#424,.T.);
#428=ORIENTED_EDGE('',*,*,#427,.T.);
#429=CARTESIAN_POINT('',(46.75,8.47425322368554,32.7693509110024));
#430=DIRECTION('',(1.,0.,0.));
#431=DIRECTION('',(0.,1.,0.));
#432=AXIS2_PLACEMENT_3D('',#429,#430,#431);
#433=CIRCLE('',#432,2.67875466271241);
#434=EDGE_CURVE('E566',#36,#426,#433,.T.);
#435=ORIENTED_EDGE('',*,*,#434,.F.);
#436=CARTESIAN_POINT('',(46.2565707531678,9.54893617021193,-184.999446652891));
#437=DIRECTION('',(0.,1.,0.));
#438=DIRECTION('',(-1.,0.,0.));
#439=AXIS2_PLACEMENT_3D('',#436,#437,#438);
#440=CIRCLE('',#439,215.315634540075);
#441=CARTESIAN_POINT('',(5.4605693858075,9.54893617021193,26.4160417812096));
#442=VERTEX_POINT('',#441);
#443=EDGE_CURVE('E505',#442,#36,#440,.T.);
#444=ORIENTED_EDGE('',*,*,#443,.F.);
#445=CARTESIAN_POINT('',(5.4605693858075,9.54893617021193,26.4160417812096));
#446=CARTESIAN_POINT('',(5.41345245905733,9.57588012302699,26.4189684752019));
#447=CARTESIAN_POINT('',(5.36615185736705,9.60246616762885,26.4222237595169));
#448=CARTESIAN_POINT('',(5.27122887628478,9.65489946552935,26.429350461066));
#449=CARTESIAN_POINT('',(5.22360672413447,9.68074718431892,26.4332214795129));
#450=CARTESIAN_POINT('',(5.12804002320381,9.73170782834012,26.4415412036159));
#451=CARTESIAN_POINT('',(5.08009557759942,9.75682097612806,26.4459897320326));
#452=CARTESIAN_POINT('',(4.98388452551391,9.80631539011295,26.4554275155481));
#453=CARTESIAN_POINT('',(4.93561792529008,9.83069667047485,26.4604167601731));
#454=CARTESIAN_POINT('',(4.83875885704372,9.87873149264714,26.4709004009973));
#455=CARTESIAN_POINT('',(4.79016628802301,9.90238479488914,26.4763949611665));
#456=CARTESIAN_POINT('',(4.69265247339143,9.94896650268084,26.4878544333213));
#457=CARTESIAN_POINT('',(4.6437310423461,9.97189444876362,26.4938196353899));
#458=CARTESIAN_POINT('',(4.59466619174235,9.99445058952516,26.5));
#459=B_SPLINE_CURVE_WITH_KNOTS('',3,(#445,#446,#447,#448,#449,#450,#451,#452,#453,#454,#455,
#456,#457,#458),.UNSPECIFIED.,.F.,.F.,(4,2,2,2,2,2,4),(0.,0.163064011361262,0.326022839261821,
0.488931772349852,0.651837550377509,0.814796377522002,0.977856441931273),.UNSPECIFIED.);
#460=EDGE_CURVE('E519',#442,#357,#459,.T.);
#461=ORIENTED_EDGE('',*,*,#460,.T.);
#462=EDGE_LOOP('',(#359,#404,#419,#428,#435,#444,#461));
#463=FACE_BOUND('',#462,.T.);
#464=ADVANCED_FACE('F525',(#463),#312,.F.);
#465=CARTESIAN_POINT('',(-27.3662254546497,9.55000000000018,19.5618100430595));
#466=DIRECTION('',(0.940144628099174,0.,0.340775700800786));
#467=DIRECTION('',(0.,1.,0.));
#468=AXIS2_PLACEMENT_3D('',#465,#466,#467);
#469=CIRCLE('',#468,1.59999999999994);
#470=CARTESIAN_POINT('',(46.2565707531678,0.,-184.999446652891));
#471=DIRECTION('',(0.,1.,0.));
#472=AXIS1_PLACEMENT('',#470,#471);
#473=SURFACE_OF_REVOLUTION('',#469,#472);
#474=CARTESIAN_POINT('',(-4.53826722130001,9.87931034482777,28.));
#475=CARTESIAN_POINT('',(-4.52605574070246,9.89277220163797,28.));
#476=CARTESIAN_POINT('',(-4.51342694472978,9.90584132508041,28.));
#477=CARTESIAN_POINT('',(-4.48747834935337,9.93125473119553,28.));
#478=CARTESIAN_POINT('',(-4.47415912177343,9.94359959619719,28.));
#479=CARTESIAN_POINT('',(-4.43355841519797,9.97948610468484,28.));
#480=CARTESIAN_POINT('',(-4.40544269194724,10.0020836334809,28.));
#481=CARTESIAN_POINT('',(-4.34772267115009,10.0451551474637,28.));
#482=CARTESIAN_POINT('',(-4.31812066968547,10.0656322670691,28.));
#483=CARTESIAN_POINT('',(-4.2581981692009,10.1046062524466,28.));
#484=CARTESIAN_POINT('',(-4.22789214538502,10.123125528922,28.));
#485=CARTESIAN_POINT('',(-4.1664120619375,10.158781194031,28.));
#486=CARTESIAN_POINT('',(-4.13523657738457,10.1759151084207,28.));
#487=CARTESIAN_POINT('',(-4.07222642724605,10.2089821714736,28.));
#488=CARTESIAN_POINT('',(-4.04039123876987,10.2249143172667,28.));
#489=CARTESIAN_POINT('',(-3.93367289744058,10.276173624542,28.));
#490=CARTESIAN_POINT('',(-3.85768509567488,10.3092044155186,28.));
#491=CARTESIAN_POINT('',(-3.70404365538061,10.3710642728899,28.));
#492=CARTESIAN_POINT('',(-3.62638971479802,10.3998925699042,28.));
#493=CARTESIAN_POINT('',(-3.46987124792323,10.4542650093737,28.));
#494=CARTESIAN_POINT('',(-3.39100571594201,10.4798062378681,28.));
#495=CARTESIAN_POINT('',(-3.23244580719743,10.5281938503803,28.));
#496=CARTESIAN_POINT('',(-3.15275129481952,10.5510397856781,28.));
#497=CARTESIAN_POINT('',(-2.99095980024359,10.594955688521,28.));
#498=CARTESIAN_POINT('',(-2.90884898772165,10.6159744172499,28.));
#499=CARTESIAN_POINT('',(-2.74420799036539,10.65597528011,28.));
#500=CARTESIAN_POINT('',(-2.6616782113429,10.6749590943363,28.));
#501=CARTESIAN_POINT('',(-2.49626562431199,10.7111645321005,28.));
#502=CARTESIAN_POINT('',(-2.41338295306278,10.7283867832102,28.));
#503=CARTESIAN_POINT('',(-2.24731773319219,10.7612788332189,28.));
#504=CARTESIAN_POINT('',(-2.16413520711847,10.7769487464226,28.));
#505=CARTESIAN_POINT('',(-1.99310002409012,10.8076944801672,28.));
#506=CARTESIAN_POINT('',(-1.90523380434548,10.8226946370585,28.));
#507=CARTESIAN_POINT('',(-1.72926281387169,10.8513098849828,28.));
#508=CARTESIAN_POINT('',(-1.64115800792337,10.8649247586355,28.));
#509=CARTESIAN_POINT('',(-1.46474875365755,10.8908935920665,28.));
#510=CARTESIAN_POINT('',(-1.37644427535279,10.9032473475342,28.));
#511=CARTESIAN_POINT('',(-1.19967154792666,10.9267961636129,28.));
#512=CARTESIAN_POINT('',(-1.11120328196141,10.9379910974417,28.));
#513=CARTESIAN_POINT('',(-0.937614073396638,10.9588889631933,28.));
#514=CARTESIAN_POINT('',(-0.852498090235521,10.9686332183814,28.));
#515=CARTESIAN_POINT('',(-0.682174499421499,10.9871951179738,28.));
#516=CARTESIAN_POINT('',(-0.596966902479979,10.9960128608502,28.));
#517=CARTESIAN_POINT('',(-0.426488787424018,11.0127772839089,28.));
#518=CARTESIAN_POINT('',(-0.341218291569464,11.0207241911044,28.));
#519=CARTESIAN_POINT('',(-0.170641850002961,11.0357935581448,28.));
#520=CARTESIAN_POINT('',(-0.0853359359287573,11.0429163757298,28.));
#521=CARTESIAN_POINT('',(0.,11.0496525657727,28.));
#522=B_SPLINE_CURVE_WITH_KNOTS('',3,(#474,#475,#476,#477,#478,#479,#480,#481,#482,#483,#484,
#485,#486,#487,#488,#489,#490,#491,#492,#493,#494,#495,#496,#497,#498,#499,#500,#501,#502,#503,
#504,#505,#506,#507,#508,#509,#510,#511,#512,#513,#514,#515,#516,#517,#518,#519,#520,#521),
.UNSPECIFIED.,.F.,.F.,(4,2,2,2,2,2,2,2,2,2,2,2,2,2,2,2,2,2,2,2,2,2,2,4),(0.,0.0545008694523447,
0.108957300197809,0.217035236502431,0.324951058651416,0.431454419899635,0.538143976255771,
0.644921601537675,0.893291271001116,1.14170635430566,1.39034016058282,1.63901530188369,
1.89326022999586,2.14729360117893,2.40123615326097,2.65515999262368,2.92255979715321,
3.19000149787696,3.45748645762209,3.7250006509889,3.98201112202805,4.23899424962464,
4.49591022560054,4.75271425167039),.UNSPECIFIED.);
#523=CARTESIAN_POINT('',(-3.9675566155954,10.2595562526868,28.));
#524=VERTEX_POINT('',#523);
#525=CARTESIAN_POINT('',(-2.5943064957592,10.6896947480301,28.));
#526=VERTEX_POINT('',#525);
#527=EDGE_CURVE('E764',#524,#526,#522,.T.);
#528=ORIENTED_EDGE('',*,*,#527,.F.);
#529=CARTESIAN_POINT('',(-3.9675566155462,10.2595562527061,28.0000000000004));
#530=CARTESIAN_POINT('',(-4.01690795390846,10.2404713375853,27.9980651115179));
#531=CARTESIAN_POINT('',(-4.06611219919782,10.2210336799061,27.9958404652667));
#532=CARTESIAN_POINT('',(-4.1641692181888,10.1814776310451,27.990763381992));
#533=CARTESIAN_POINT('',(-4.21302223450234,10.1613597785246,27.987911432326));
#534=CARTESIAN_POINT('',(-4.31037579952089,10.1204469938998,27.9815299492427));
#535=CARTESIAN_POINT('',(-4.35887648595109,10.0996523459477,27.9780006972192));
#536=CARTESIAN_POINT('',(-4.45552642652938,10.0573886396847,27.9702126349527));
#537=CARTESIAN_POINT('',(-4.50367566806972,10.0359195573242,27.9659537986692));
#538=CARTESIAN_POINT('',(-4.59961660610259,9.99231226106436,27.9566528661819));
#539=CARTESIAN_POINT('',(-4.64740816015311,9.97017379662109,27.9516104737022));
#540=CARTESIAN_POINT('',(-4.74262936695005,9.925232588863,27.9406852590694));
#541=CARTESIAN_POINT('',(-4.79005869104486,9.90242931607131,27.934801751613));
#542=CARTESIAN_POINT('',(-4.8372747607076,9.87931034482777,27.9284725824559));
#543=B_SPLINE_CURVE_WITH_KNOTS('',3,(#529,#530,#531,#532,#533,#534,#535,#536,#537,#538,#539,
#540,#541,#542),.UNSPECIFIED.,.F.,.F.,(4,2,2,2,2,2,4),(0.,0.158843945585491,0.317564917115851,
0.476220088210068,0.634880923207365,0.793601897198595,0.952452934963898),.UNSPECIFIED.);
#544=CARTESIAN_POINT('',(-4.8372747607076,9.87931034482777,27.9284725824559));
#545=VERTEX_POINT('',#544);
#546=EDGE_CURVE('E449',#524,#545,#543,.T.);
#547=ORIENTED_EDGE('',*,*,#546,.T.);
#548=CARTESIAN_POINT('',(46.2565707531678,9.87931034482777,-184.999446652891));
#549=DIRECTION('',(0.,1.,0.));
#550=DIRECTION('',(-1.,0.,0.));
#551=AXIS2_PLACEMENT_3D('',#548,#549,#550);
#552=CIRCLE('',#551,218.972326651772);
#553=CARTESIAN_POINT('',(46.75,9.87931034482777,33.9723240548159));
#554=VERTEX_POINT('',#553);
#555=EDGE_CURVE('E499',#545,#554,#552,.T.);
#556=ORIENTED_EDGE('',*,*,#555,.T.);
#557=CARTESIAN_POINT('',(46.75,9.55000000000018,32.4065799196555));
#558=DIRECTION('',(1.,0.,0.));
#559=DIRECTION('',(0.,1.,0.));
#560=AXIS2_PLACEMENT_3D('',#557,#558,#559);
#561=CIRCLE('',#560,1.59999999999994);
#562=EDGE_CURVE('E569',#426,#554,#561,.T.);
#563=ORIENTED_EDGE('',*,*,#562,.F.);
#564=ORIENTED_EDGE('',*,*,#427,.F.);
#565=CARTESIAN_POINT('',(0.,11.1437941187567,27.5733366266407));
#566=CARTESIAN_POINT('',(0.,11.1375132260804,27.6461630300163));
#567=CARTESIAN_POINT('',(0.,11.1264600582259,27.7184865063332));
#568=CARTESIAN_POINT('',(0.,11.105509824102,27.8134739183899));
#569=CARTESIAN_POINT('',(0.,11.0997631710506,27.8370707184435));
#570=CARTESIAN_POINT('',(0.,11.0872325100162,27.8840366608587));
#571=CARTESIAN_POINT('',(0.,11.0804465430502,27.9074052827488));
#572=CARTESIAN_POINT('',(0.,11.0658293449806,27.9539115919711));
#573=CARTESIAN_POINT('',(0.,11.0579942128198,27.9770480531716));
#574=CARTESIAN_POINT('',(0.,11.0496525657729,27.9999999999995));
#575=B_SPLINE_CURVE_WITH_KNOTS('',3,(#565,#566,#567,#568,#569,#570,#571,#572,#573,#574),
.UNSPECIFIED.,.F.,.F.,(4,2,2,2,4),(0.,0.218933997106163,0.291772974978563,0.364750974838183,
0.438008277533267),.UNSPECIFIED.);
#576=CARTESIAN_POINT('',(0.,11.0496525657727,28.));
#577=VERTEX_POINT('',#576);
#578=EDGE_CURVE('E376',#417,#577,#575,.T.);
#579=ORIENTED_EDGE('',*,*,#578,.T.);
#580=CARTESIAN_POINT('',(-0.898553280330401,10.9632386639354,28.));
#581=VERTEX_POINT('',#580);
#582=EDGE_CURVE('E765',#581,#577,#522,.T.);
#583=ORIENTED_EDGE('',*,*,#582,.F.);
#584=CARTESIAN_POINT('',(-0.898553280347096,10.963238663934,28.));
#585=CARTESIAN_POINT('',(-0.969984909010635,10.9573848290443,27.9954843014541));
#586=CARTESIAN_POINT('',(-1.04141270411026,10.9508270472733,27.9919674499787));
#587=CARTESIAN_POINT('',(-1.18406327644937,10.9363211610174,27.9865828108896));
#588=CARTESIAN_POINT('',(-1.2552861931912,10.9283755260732,27.9847121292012));
#589=CARTESIAN_POINT('',(-1.39751603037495,10.9110988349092,27.9822589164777));
#590=CARTESIAN_POINT('',(-1.46852308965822,10.9017690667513,27.9816751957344));
#591=CARTESIAN_POINT('',(-1.61031754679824,10.8817279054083,27.981472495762));
#592=CARTESIAN_POINT('',(-1.6811050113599,10.8710169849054,27.9818531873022));
#593=CARTESIAN_POINT('',(-1.8224290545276,10.8482198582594,27.9832925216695));
#594=CARTESIAN_POINT('',(-1.89296570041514,10.836134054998,27.9843509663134));
#595=CARTESIAN_POINT('',(-2.03382190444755,10.8105825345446,27.9868957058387));
#596=CARTESIAN_POINT('',(-2.10414131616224,10.7971160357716,27.988382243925));
#597=CARTESIAN_POINT('',(-2.24456739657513,10.76879995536,27.9915627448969));
#598=CARTESIAN_POINT('',(-2.31467379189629,10.753949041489,27.9932569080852));
#599=CARTESIAN_POINT('',(-2.45467710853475,10.7228591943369,27.9966632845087));
#600=CARTESIAN_POINT('',(-2.5245736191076,10.7066184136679,27.9983755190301));
#601=CARTESIAN_POINT('',(-2.5943064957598,10.6896947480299,28.));
#602=B_SPLINE_CURVE_WITH_KNOTS('',3,(#584,#585,#586,#587,#588,#589,#590,#591,#592,#593,#594,
#595,#596,#597,#598,#599,#600,#601),.UNSPECIFIED.,.F.,.F.,(4,2,2,2,2,2,2,2,4),(0.,
0.215415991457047,0.430452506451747,0.645290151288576,0.860054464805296,1.07475600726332,
1.28957976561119,1.50461242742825,1.71993548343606),.UNSPECIFIED.);
#603=EDGE_CURVE('E455',#581,#526,#602,.T.);
#604=ORIENTED_EDGE('',*,*,#603,.T.);
#605=EDGE_LOOP('',(#528,#547,#556,#563,#564,#579,#583,#604));
#606=FACE_BOUND('',#605,.T.);
#607=ADVANCED_FACE('F391',(#606),#473,.F.);
#608=CARTESIAN_POINT('',(-11.8927663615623,0.,-23.1269421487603));
#609=DIRECTION('',(0.940144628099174,0.,0.340775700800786));
#610=DIRECTION('',(0.,1.,0.));
#611=AXIS2_PLACEMENT_3D('',#608,#609,#610);
#612=CIRCLE('',#611,48.0000000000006);
#613=CARTESIAN_POINT('',(46.2565707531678,0.,-184.999446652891));
#614=DIRECTION('',(0.,1.,0.));
#615=AXIS1_PLACEMENT('',#613,#614);
#616=SURFACE_OF_REVOLUTION('',#612,#615);
#617=ORIENTED_EDGE('',*,*,#555,.F.);
#618=CARTESIAN_POINT('',(-4.8372747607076,9.87931034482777,27.9284725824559));
#619=CARTESIAN_POINT('',(-5.11125527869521,9.74520228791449,27.8917302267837));
#620=CARTESIAN_POINT('',(-5.37990658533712,9.59949129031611,27.8576368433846));
#621=CARTESIAN_POINT('',(-5.9045802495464,9.2859622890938,27.7944453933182));
#622=CARTESIAN_POINT('',(-6.16060333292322,9.11814555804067,27.7653470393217));
#623=CARTESIAN_POINT('',(-6.65784376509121,8.76165908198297,27.7118644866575));
#624=CARTESIAN_POINT('',(-6.89907505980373,8.5730094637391,27.6874757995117));
#625=CARTESIAN_POINT('',(-7.36518970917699,8.17604276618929,27.6429790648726));
#626=CARTESIAN_POINT('',(-7.59007328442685,7.9677259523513,27.6228709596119));
#627=CARTESIAN_POINT('',(-8.02192010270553,7.53277928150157,27.586484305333));
#628=CARTESIAN_POINT('',(-8.22887498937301,7.30614097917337,27.5702075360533));
#629=CARTESIAN_POINT('',(-8.62322119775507,6.83623697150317,27.5410234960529));
#630=CARTESIAN_POINT('',(-8.81061243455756,6.59297119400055,27.5281162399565));
#631=CARTESIAN_POINT('',(-9.16443653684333,6.09157115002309,27.5051958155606));
#632=CARTESIAN_POINT('',(-9.33087231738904,5.83343895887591,27.495182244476));
#633=CARTESIAN_POINT('',(-9.64161155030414,5.3041036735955,27.4775846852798));
#634=CARTESIAN_POINT('',(-9.78591507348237,5.03290062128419,27.4700006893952));
#635=CARTESIAN_POINT('',(-10.0516486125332,4.478727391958,27.456818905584));
#636=CARTESIAN_POINT('',(-10.1730274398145,4.19573256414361,27.4512255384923));
#637=CARTESIAN_POINT('',(-10.3916476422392,3.62054140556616,27.4416665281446));
#638=CARTESIAN_POINT('',(-10.4888889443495,3.32834504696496,27.4377008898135));
#639=CARTESIAN_POINT('',(-10.6585543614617,2.73677173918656,27.4310784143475));
#640=CARTESIAN_POINT('',(-10.730974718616,2.4373937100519,27.4284217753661));
#641=CARTESIAN_POINT('',(-10.8504640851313,1.83361309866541,27.4241739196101));
#642=CARTESIAN_POINT('',(-10.8975330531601,1.52921050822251,27.4225827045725));
#643=CARTESIAN_POINT('',(-10.9661093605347,0.916426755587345,27.4202996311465));
#644=CARTESIAN_POINT('',(-10.9875241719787,0.608035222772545,27.4196110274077));
#645=CARTESIAN_POINT('',(-11.0043312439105,-0.00945743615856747,27.4190687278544));
#646=CARTESIAN_POINT('',(-10.9997234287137,-0.318558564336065,27.4192150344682));
#647=CARTESIAN_POINT('',(-10.9645185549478,-0.935265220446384,27.4203587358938));
#648=CARTESIAN_POINT('',(-10.9339223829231,-1.2428707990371,27.4213561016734));
#649=CARTESIAN_POINT('',(-10.8469599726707,-1.85441249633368,27.4243087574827));
#650=CARTESIAN_POINT('',(-10.7905937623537,-2.15834861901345,27.426264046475));
#651=CARTESIAN_POINT('',(-10.6524440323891,-2.76060758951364,27.4313284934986));
#652=CARTESIAN_POINT('',(-10.570642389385,-3.05892627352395,27.4344384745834));
#653=CARTESIAN_POINT('',(-10.3822205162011,-3.64760308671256,27.442087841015));
#654=CARTESIAN_POINT('',(-10.2756001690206,-3.93796117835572,27.4466272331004));
#655=CARTESIAN_POINT('',(-10.0383008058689,-4.50866105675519,27.4574833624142));
#656=CARTESIAN_POINT('',(-9.90762031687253,-4.78900222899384,27.4638002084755));
#657=CARTESIAN_POINT('',(-9.62315328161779,-5.33763999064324,27.4786184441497));
#658=CARTESIAN_POINT('',(-9.46936712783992,-5.60593678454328,27.4871197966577));
#659=CARTESIAN_POINT('',(-9.13998617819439,-6.12828537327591,27.5067488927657));
#660=CARTESIAN_POINT('',(-8.96441517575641,-6.38235227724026,27.5178737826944));
#661=CARTESIAN_POINT('',(-8.59262510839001,-6.87473399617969,27.5432325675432));
#662=CARTESIAN_POINT('',(-8.39640598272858,-7.11304876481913,27.5574664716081));
#663=CARTESIAN_POINT('',(-7.98485602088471,-7.57212250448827,27.5895230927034));
#664=CARTESIAN_POINT('',(-7.76953386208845,-7.79288936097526,27.6073441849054));
#665=CARTESIAN_POINT('',(-7.32141614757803,-8.21533439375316,27.6470386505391));
#666=CARTESIAN_POINT('',(-7.08862500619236,-8.41701736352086,27.6689110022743));
#667=CARTESIAN_POINT('',(-6.53623573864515,-8.85640977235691,27.7242694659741));
#668=CARTESIAN_POINT('',(-6.21125658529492,-9.08724753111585,27.7592789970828));
#669=CARTESIAN_POINT('',(-5.70746530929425,-9.40554757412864,27.8179830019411));
#670=CARTESIAN_POINT('',(-5.53691709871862,-9.50693792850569,27.8385690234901));
#671=CARTESIAN_POINT('',(-5.19076318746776,-9.7002710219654,27.881889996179));
#672=CARTESIAN_POINT('',(-5.01515640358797,-9.79221171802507,27.9046254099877));
#673=CARTESIAN_POINT('',(-4.8372747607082,-9.87931034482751,27.9284725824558));
#674=B_SPLINE_CURVE_WITH_KNOTS('',3,(#618,#619,#620,#621,#622,#623,#624,#625,#626,#627,#628,
#629,#630,#631,#632,#633,#634,#635,#636,#637,#638,#639,#640,#641,#642,#643,#644,#645,#646,#647,
#648,#649,#650,#651,#652,#653,#654,#655,#656,#657,#658,#659,#660,#661,#662,#663,#664,#665,#666,
#667,#668,#669,#670,#671,#672,#673),.UNSPECIFIED.,.F.,.F.,(4,2,2,2,2,2,2,2,2,2,2,2,2,2,2,2,2,2,
2,2,2,2,2,2,2,2,2,4),(0.,0.921459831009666,1.84286663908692,2.76339093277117,3.68390280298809,
4.60484143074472,5.52578405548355,6.44659842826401,7.3674098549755,8.29025366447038,
9.21310026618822,10.1360865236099,11.059074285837,11.9853810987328,12.9116906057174,
13.8379685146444,14.7642454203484,15.6911838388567,16.6181266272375,17.5451261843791,
18.4721099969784,19.3980901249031,20.3240729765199,21.2496373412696,22.1749686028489,
23.3726920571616,23.9708670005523,24.5691709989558),.UNSPECIFIED.);
#675=CARTESIAN_POINT('',(-4.8372747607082,-9.87931034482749,27.9284725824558));
#676=VERTEX_POINT('',#675);
#677=EDGE_CURVE('E443',#545,#676,#674,.T.);
#678=ORIENTED_EDGE('',*,*,#677,.T.);
#679=CARTESIAN_POINT('',(46.2565707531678,-9.87931034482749,-184.999446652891));
#680=DIRECTION('',(0.,1.,0.));
#681=DIRECTION('',(-1.,0.,0.));
#682=AXIS2_PLACEMENT_3D('',#679,#680,#681);
#683=CIRCLE('',#682,218.972326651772);
#684=CARTESIAN_POINT('',(46.75,-9.87931034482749,33.9723240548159));
#685=VERTEX_POINT('',#684);
#686=EDGE_CURVE('E495',#676,#685,#683,.T.);
#687=ORIENTED_EDGE('',*,*,#686,.T.);
#688=CARTESIAN_POINT('',(46.75,0.,-13.));
#689=DIRECTION('',(1.,0.,0.));
#690=DIRECTION('',(0.,1.,0.));
#691=AXIS2_PLACEMENT_3D('',#688,#689,#690);
#692=CIRCLE('',#691,48.0000000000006);
#693=EDGE_CURVE('E572',#554,#685,#692,.T.);
#694=ORIENTED_EDGE('',*,*,#693,.F.);
#695=EDGE_LOOP('',(#617,#678,#687,#694));
#696=FACE_BOUND('',#695,.T.);
#697=ADVANCED_FACE('F479',(#696),#616,.F.);
#698=CARTESIAN_POINT('',(-27.3662254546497,-9.54999999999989,19.5618100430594));
#699=DIRECTION('',(0.940144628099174,0.,0.340775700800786));
#700=DIRECTION('',(0.,1.,0.));
#701=AXIS2_PLACEMENT_3D('',#698,#699,#700);
#702=CIRCLE('',#701,1.6);
#703=CARTESIAN_POINT('',(46.2565707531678,0.,-184.999446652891));
#704=DIRECTION('',(0.,1.,0.));
#705=AXIS1_PLACEMENT('',#703,#704);
#706=SURFACE_OF_REVOLUTION('',#702,#705);
#707=CARTESIAN_POINT('',(0.,-11.0496525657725,28.));
#708=CARTESIAN_POINT('',(-0.1028303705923,-11.0415342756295,28.));
#709=CARTESIAN_POINT('',(-0.205617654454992,-11.0328561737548,28.));
#710=CARTESIAN_POINT('',(-0.411324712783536,-11.014272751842,28.));
#711=CARTESIAN_POINT('',(-0.51424423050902,-11.0043645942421,28.));
#712=CARTESIAN_POINT('',(-0.72012093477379,-10.9832333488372,28.));
#713=CARTESIAN_POINT('',(-0.823077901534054,-10.9720081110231,28.));
#714=CARTESIAN_POINT('',(-1.02893197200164,-10.9481359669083,28.));
#715=CARTESIAN_POINT('',(-1.13182891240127,-10.9354876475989,28.));
#716=CARTESIAN_POINT('',(-1.33746338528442,-10.9086433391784,28.));
#717=CARTESIAN_POINT('',(-1.44020083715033,-10.8944467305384,28.));
#718=CARTESIAN_POINT('',(-1.65257899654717,-10.8633023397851,28.));
#719=CARTESIAN_POINT('',(-1.76220180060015,-10.8462317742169,28.));
#720=CARTESIAN_POINT('',(-1.98103877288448,-10.8099065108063,28.));
#721=CARTESIAN_POINT('',(-2.0902530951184,-10.7906527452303,28.));
#722=CARTESIAN_POINT('',(-2.30814197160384,-10.7496538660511,28.));
#723=CARTESIAN_POINT('',(-2.41681683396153,-10.7279104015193,28.));
#724=CARTESIAN_POINT('',(-2.63347302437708,-10.681519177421,28.));
#725=CARTESIAN_POINT('',(-2.7414547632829,-10.6568733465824,28.));
#726=CARTESIAN_POINT('',(-2.95654971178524,-10.6041021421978,28.));
#727=CARTESIAN_POINT('',(-3.06366312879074,-10.5759776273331,28.));
#728=CARTESIAN_POINT('',(-3.22084067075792,-10.5312836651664,28.));
#729=CARTESIAN_POINT('',(-3.27138116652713,-10.5163838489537,28.));
#730=CARTESIAN_POINT('',(-3.37212581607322,-10.4854798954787,28.));
#731=CARTESIAN_POINT('',(-3.42232996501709,-10.4694757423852,28.));
#732=CARTESIAN_POINT('',(-3.52232348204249,-10.4362138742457,28.));
#733=CARTESIAN_POINT('',(-3.57211284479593,-10.4189561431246,28.));
#734=CARTESIAN_POINT('',(-3.67046871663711,-10.383250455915,28.));
#735=CARTESIAN_POINT('',(-3.71904255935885,-10.3648228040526,27.9999999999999));
#736=CARTESIAN_POINT('',(-3.81554113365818,-10.3263258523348,28.0000000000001));
#737=CARTESIAN_POINT('',(-3.86346583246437,-10.3062564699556,28.0000000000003));
#738=CARTESIAN_POINT('',(-3.95848096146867,-10.264154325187,27.9999999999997));
#739=CARTESIAN_POINT('',(-4.00557099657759,-10.2421206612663,27.9999999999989));
#740=CARTESIAN_POINT('',(-4.08150811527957,-10.2041891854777,27.9999999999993));
#741=CARTESIAN_POINT('',(-4.11071151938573,-10.1890049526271,27.9999999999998));
#742=CARTESIAN_POINT('',(-4.16850341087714,-10.1575450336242,28.0000000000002));
#743=CARTESIAN_POINT('',(-4.19709228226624,-10.1412700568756,28.0000000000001));
#744=CARTESIAN_POINT('',(-4.25346589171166,-10.1074677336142,28.));
#745=CARTESIAN_POINT('',(-4.28125178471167,-10.089942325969,28.));
#746=CARTESIAN_POINT('',(-4.33617913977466,-10.0531573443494,28.));
#747=CARTESIAN_POINT('',(-4.36330764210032,-10.0338782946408,28.));
#748=CARTESIAN_POINT('',(-4.41621781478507,-9.99345746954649,28.));
#749=CARTESIAN_POINT('',(-4.44199773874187,-9.97231336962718,28.));
#750=CARTESIAN_POINT('',(-4.47927135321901,-9.93887561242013,28.));
#751=CARTESIAN_POINT('',(-4.49150115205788,-9.92740207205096,28.));
#752=CARTESIAN_POINT('',(-4.51536239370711,-9.90383435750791,28.));
#753=CARTESIAN_POINT('',(-4.52699342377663,-9.89173976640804,28.));
#754=CARTESIAN_POINT('',(-4.5382672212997,-9.87931034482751,28.));
#755=B_SPLINE_CURVE_WITH_KNOTS('',3,(#707,#708,#709,#710,#711,#712,#713,#714,#715,#716,#717,
#718,#719,#720,#721,#722,#723,#724,#725,#726,#727,#728,#729,#730,#731,#732,#733,#734,#735,#736,
#737,#738,#739,#740,#741,#742,#743,#744,#745,#746,#747,#748,#749,#750,#751,#752,#753,#754),
.UNSPECIFIED.,.F.,.F.,(4,2,2,2,2,2,2,2,2,2,2,2,2,2,2,2,2,2,2,2,2,2,2,4),(0.,0.309451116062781,
0.619629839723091,0.930322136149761,1.24132569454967,1.55245415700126,1.8852662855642,
2.21793682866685,2.55038828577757,2.88262005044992,3.21476996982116,3.37283312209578,
3.53089854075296,3.68896598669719,3.8447961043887,4.00063405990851,4.15654391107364,
4.25526989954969,4.35393228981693,4.45244489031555,4.55222994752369,4.65214117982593,
4.70242936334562,4.75275175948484),.UNSPECIFIED.);
#756=CARTESIAN_POINT('',(0.,-11.0496525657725,28.));
#757=VERTEX_POINT('',#756);
#758=CARTESIAN_POINT('',(-0.898553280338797,-10.9632386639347,28.));
#759=VERTEX_POINT('',#758);
#760=EDGE_CURVE('E632',#757,#759,#755,.T.);
#761=ORIENTED_EDGE('',*,*,#760,.F.);
#762=CARTESIAN_POINT('',(0.,-11.0496525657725,28.));
#763=CARTESIAN_POINT('',(0.,-11.0579942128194,27.9770480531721));
#764=CARTESIAN_POINT('',(0.,-11.0658293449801,27.9539115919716));
#765=CARTESIAN_POINT('',(0.,-11.0804465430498,27.9074052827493));
#766=CARTESIAN_POINT('',(0.,-11.0872325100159,27.8840366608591));
#767=CARTESIAN_POINT('',(0.,-11.0997631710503,27.8370707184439));
#768=CARTESIAN_POINT('',(0.,-11.1055098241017,27.8134739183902));
#769=CARTESIAN_POINT('',(0.,-11.1264600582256,27.7184865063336));
#770=CARTESIAN_POINT('',(0.,-11.1375132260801,27.6461630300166));
#771=CARTESIAN_POINT('',(0.,-11.1437941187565,27.5733366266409));
#772=B_SPLINE_CURVE_WITH_KNOTS('',3,(#762,#763,#764,#765,#766,#767,#768,#769,#770,#771),
.UNSPECIFIED.,.F.,.F.,(4,2,2,2,4),(0.,0.0732573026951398,0.146235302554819,0.219074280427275,
0.438008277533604),.UNSPECIFIED.);
#773=EDGE_CURVE('E462',#757,#160,#772,.T.);
#774=ORIENTED_EDGE('',*,*,#773,.T.);
#775=ORIENTED_EDGE('',*,*,#163,.T.);
#776=CARTESIAN_POINT('',(46.75,-9.54999999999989,32.4065799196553));
#777=DIRECTION('',(1.,0.,0.));
#778=DIRECTION('',(0.,1.,0.));
#779=AXIS2_PLACEMENT_3D('',#776,#777,#778);
#780=CIRCLE('',#779,1.6);
#781=EDGE_CURVE('E496',#685,#162,#780,.T.);
#782=ORIENTED_EDGE('',*,*,#781,.F.);
#783=ORIENTED_EDGE('',*,*,#686,.F.);
#784=CARTESIAN_POINT('',(-4.8372747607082,-9.87931034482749,27.9284725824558));
#785=CARTESIAN_POINT('',(-4.79005869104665,-9.90242931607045,27.9348017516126));
#786=CARTESIAN_POINT('',(-4.74262936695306,-9.92523258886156,27.9406852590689));
#787=CARTESIAN_POINT('',(-4.64740816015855,-9.97017379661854,27.9516104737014));
#788=CARTESIAN_POINT('',(-4.59961660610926,-9.99231226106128,27.956652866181));
#789=CARTESIAN_POINT('',(-4.50367566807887,-10.0359195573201,27.9659537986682));
#790=CARTESIAN_POINT('',(-4.45552642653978,-10.0573886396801,27.9702126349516));
#791=CARTESIAN_POINT('',(-4.358876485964,-10.0996523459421,27.9780006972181));
#792=CARTESIAN_POINT('',(-4.31037579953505,-10.1204469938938,27.9815299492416));
#793=CARTESIAN_POINT('',(-4.21302223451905,-10.1613597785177,27.9879114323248));
#794=CARTESIAN_POINT('',(-4.16416921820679,-10.1814776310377,27.9907633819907));
#795=CARTESIAN_POINT('',(-4.06611219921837,-10.2210336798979,27.9958404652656));
#796=CARTESIAN_POINT('',(-4.01690795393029,-10.2404713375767,27.998065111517));
#797=CARTESIAN_POINT('',(-3.9675566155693,-10.2595562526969,28.));
#798=B_SPLINE_CURVE_WITH_KNOTS('',3,(#784,#785,#786,#787,#788,#789,#790,#791,#792,#793,#794,
#795,#796,#797),.UNSPECIFIED.,.F.,.F.,(4,2,2,2,2,2,4),(0.,0.15885103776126,0.317572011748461,
0.476232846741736,0.634888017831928,0.793608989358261,0.952452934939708),.UNSPECIFIED.);
#799=CARTESIAN_POINT('',(-3.9675566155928,-10.2595562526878,28.));
#800=VERTEX_POINT('',#799);
#801=EDGE_CURVE('E437',#676,#800,#798,.T.);
#802=ORIENTED_EDGE('',*,*,#801,.T.);
#803=CARTESIAN_POINT('',(-2.5943064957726,-10.6896947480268,28.));
#804=VERTEX_POINT('',#803);
#805=EDGE_CURVE('E631',#804,#800,#755,.T.);
#806=ORIENTED_EDGE('',*,*,#805,.F.);
#807=CARTESIAN_POINT('',(-2.5943064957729,-10.6896947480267,28.));
#808=CARTESIAN_POINT('',(-2.52457361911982,-10.706618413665,27.99837551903));
#809=CARTESIAN_POINT('',(-2.45467710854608,-10.7228591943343,27.9966632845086));
#810=CARTESIAN_POINT('',(-2.31467379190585,-10.7539490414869,27.993256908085));
#811=CARTESIAN_POINT('',(-2.24456739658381,-10.7687999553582,27.9915627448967));
#812=CARTESIAN_POINT('',(-2.10414131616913,-10.7971160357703,27.9883822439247));
#813=CARTESIAN_POINT('',(-2.03382190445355,-10.8105825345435,27.9868957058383));
#814=CARTESIAN_POINT('',(-1.89296570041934,-10.8361340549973,27.984350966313));
#815=CARTESIAN_POINT('',(-1.8224290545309,-10.8482198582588,27.9832925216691));
#816=CARTESIAN_POINT('',(-1.68110501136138,-10.8710169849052,27.9818531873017));
#817=CARTESIAN_POINT('',(-1.61031754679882,-10.8817279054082,27.9814724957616));
#818=CARTESIAN_POINT('',(-1.46852308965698,-10.9017690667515,27.9816751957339));
#819=CARTESIAN_POINT('',(-1.3975160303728,-10.9110988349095,27.9822589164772));
#820=CARTESIAN_POINT('',(-1.25528619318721,-10.9283755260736,27.9847121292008));
#821=CARTESIAN_POINT('',(-1.18406327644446,-10.936321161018,27.9865828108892));
#822=CARTESIAN_POINT('',(-1.04141270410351,-10.9508270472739,27.9919674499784));
#823=CARTESIAN_POINT('',(-0.96998490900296,-10.957384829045,27.9954843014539));
#824=CARTESIAN_POINT('',(-0.898553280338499,-10.9632386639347,28.));
#825=B_SPLINE_CURVE_WITH_KNOTS('',3,(#807,#808,#809,#810,#811,#812,#813,#814,#815,#816,#817,
#818,#819,#820,#821,#822,#823,#824),.UNSPECIFIED.,.F.,.F.,(4,2,2,2,2,2,2,2,4),(0.,
0.215323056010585,0.43035571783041,0.64517947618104,0.859881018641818,1.07464533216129,
1.28948297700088,1.50451949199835,1.71993548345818),.UNSPECIFIED.);
#826=EDGE_CURVE('E429',#804,#759,#825,.T.);
#827=ORIENTED_EDGE('',*,*,#826,.T.);
#828=EDGE_LOOP('',(#761,#774,#775,#782,#783,#802,#806,#827));
#829=FACE_BOUND('',#828,.T.);
#830=ADVANCED_FACE('F475',(#829),#706,.F.);
#831=CARTESIAN_POINT('',(-31.6918345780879,0.,31.4954607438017));
#832=DIRECTION('',(0.940144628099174,0.,0.340775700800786));
#833=DIRECTION('',(0.,1.,0.));
#834=AXIS2_PLACEMENT_3D('',#831,#832,#833);
#835=CIRCLE('',#834,17.6);
#836=CARTESIAN_POINT('',(46.2565707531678,0.,-184.999446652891));
#837=DIRECTION('',(0.,1.,0.));
#838=AXIS1_PLACEMENT('',#836,#837);
#839=SURFACE_OF_REVOLUTION('',#835,#838);
#840=ORIENTED_EDGE('',*,*,#292,.F.);
#841=CARTESIAN_POINT('',(5.46056938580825,-9.54893617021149,26.4160417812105));
#842=CARTESIAN_POINT('',(5.7340218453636,-9.39256816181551,26.3659144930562));
#843=CARTESIAN_POINT('',(5.99985554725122,-9.22495922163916,26.3100965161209));
#844=CARTESIAN_POINT('',(6.51490657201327,-8.86870622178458,26.1903628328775));
#845=CARTESIAN_POINT('',(6.7641325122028,-8.6800732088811,26.1264513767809));
#846=CARTESIAN_POINT('',(7.24508533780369,-8.28288099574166,25.9936978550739));
#847=CARTESIAN_POINT('',(7.47679692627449,-8.07430472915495,25.9248515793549));
#848=CARTESIAN_POINT('',(7.92144262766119,-7.63856320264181,25.7851894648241));
#849=CARTESIAN_POINT('',(8.13437411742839,-7.41139535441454,25.7143733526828));
#850=CARTESIAN_POINT('',(8.54010981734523,-6.93996644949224,25.5735382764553));
#851=CARTESIAN_POINT('',(8.73293567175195,-6.69572425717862,25.503518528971));
#852=CARTESIAN_POINT('',(9.09757597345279,-6.19120146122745,25.3666345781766));
#853=CARTESIAN_POINT('',(9.26939138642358,-5.93092159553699,25.2997702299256));
#854=CARTESIAN_POINT('',(9.59073616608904,-5.39584267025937,25.1714425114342));
#855=CARTESIAN_POINT('',(9.74027609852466,-5.12105057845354,25.1099765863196));
#856=CARTESIAN_POINT('',(10.015919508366,-4.55845019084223,24.9944101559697));
#857=CARTESIAN_POINT('',(10.1420232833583,-4.27064206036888,24.9403095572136));
#858=CARTESIAN_POINT('',(10.3687617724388,-3.68597163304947,24.8415872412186));
#859=CARTESIAN_POINT('',(10.4695702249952,-3.38918772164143,24.7969012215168));
#860=CARTESIAN_POINT('',(10.6457628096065,-2.7867908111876,24.7179869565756));
#861=CARTESIAN_POINT('',(10.7211469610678,-2.48117781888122,24.6837587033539));
#862=CARTESIAN_POINT('',(10.8455423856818,-1.86369394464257,24.6269116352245));
#863=CARTESIAN_POINT('',(10.8945648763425,-1.55182578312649,24.6042878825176));
#864=CARTESIAN_POINT('',(10.965635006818,-0.924393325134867,24.5713971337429));
#865=CARTESIAN_POINT('',(10.9876849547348,-0.608829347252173,24.561129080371));
#866=CARTESIAN_POINT('',(11.0037705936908,-0.00490154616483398,24.553642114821));
#867=CARTESIAN_POINT('',(11.0001193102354,0.283390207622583,24.5553457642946));
#868=CARTESIAN_POINT('',(10.9702246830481,0.858531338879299,24.5692457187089));
#869=CARTESIAN_POINT('',(10.9439828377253,1.14538081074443,24.5814413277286));
#870=CARTESIAN_POINT('',(10.8692124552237,1.71547764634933,24.6159755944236));
#871=CARTESIAN_POINT('',(10.8206880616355,1.99872566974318,24.6383123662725));
#872=CARTESIAN_POINT('',(10.7018784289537,2.55968761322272,24.6925021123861));
#873=CARTESIAN_POINT('',(10.6315928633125,2.83740145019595,24.7243552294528));
#874=CARTESIAN_POINT('',(10.4712619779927,3.38108213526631,24.7961202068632));
#875=CARTESIAN_POINT('',(10.3815503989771,3.64716578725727,24.8358951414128));
#876=CARTESIAN_POINT('',(10.1825375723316,4.1706527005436,24.9227645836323));
#877=CARTESIAN_POINT('',(10.0732365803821,4.42805607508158,24.9698589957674));
#878=CARTESIAN_POINT('',(9.8358144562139,4.93301688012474,25.0701879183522));
#879=CARTESIAN_POINT('',(9.7076793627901,5.18056683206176,25.1234269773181));
#880=CARTESIAN_POINT('',(9.43353001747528,5.66443678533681,25.2346446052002));
#881=CARTESIAN_POINT('',(9.28751530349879,5.90075649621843,25.2926232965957));
#882=CARTESIAN_POINT('',(8.9663270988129,6.37921546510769,25.4164948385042));
#883=CARTESIAN_POINT('',(8.78976427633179,6.62035455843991,25.4826516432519));
#884=CARTESIAN_POINT('',(8.41785148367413,7.0872331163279,25.6166659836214));
#885=CARTESIAN_POINT('',(8.22249831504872,7.31296994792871,25.6845238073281));
#886=CARTESIAN_POINT('',(7.81428105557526,7.74763122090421,25.819579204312));
#887=CARTESIAN_POINT('',(7.60144058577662,7.95657761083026,25.886777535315));
#888=CARTESIAN_POINT('',(7.15905775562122,8.356842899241,26.0181186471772));
#889=CARTESIAN_POINT('',(6.92952284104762,8.54816957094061,26.0822627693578));
#890=CARTESIAN_POINT('',(6.49696652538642,8.87974544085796,26.193923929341));
#891=CARTESIAN_POINT('',(6.29650148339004,9.02302345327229,26.2423678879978));
#892=CARTESIAN_POINT('',(5.88577291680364,9.29615203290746,26.3337292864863));
#893=CARTESIAN_POINT('',(5.6755208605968,9.42601776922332,26.3766529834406));
#894=CARTESIAN_POINT('',(5.46056938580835,9.54893617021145,26.4160417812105));
#895=B_SPLINE_CURVE_WITH_KNOTS('',3,(#841,#842,#843,#844,#845,#846,#847,#848,#849,#850,#851,
#852,#853,#854,#855,#856,#857,#858,#859,#860,#861,#862,#863,#864,#865,#866,#867,#868,#869,#870,
#871,#872,#873,#874,#875,#876,#877,#878,#879,#880,#881,#882,#883,#884,#885,#886,#887,#888,#889,
#890,#891,#892,#893,#894),.UNSPECIFIED.,.F.,.F.,(4,2,2,2,2,2,2,2,2,2,2,2,2,2,2,2,2,2,2,2,2,2,2,
2,2,2,4),(0.,0.956383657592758,1.91226714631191,2.86897607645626,3.82581842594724,
4.78161983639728,5.73737730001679,6.69267997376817,7.64797051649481,8.59650814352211,
9.5450450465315,10.4931780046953,11.4412298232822,12.3051248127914,13.1689625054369,
14.0326396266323,14.8963297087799,15.7462167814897,16.596092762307,17.4466019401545,
18.2971331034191,19.2144510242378,20.1319253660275,21.0481801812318,21.9640288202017,
22.7168036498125,23.4687175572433),.UNSPECIFIED.);
#896=EDGE_CURVE('E546',#284,#442,#895,.T.);
#897=ORIENTED_EDGE('',*,*,#896,.T.);
#898=ORIENTED_EDGE('',*,*,#443,.T.);
#899=ORIENTED_EDGE('',*,*,#112,.F.);
#900=EDGE_LOOP('',(#840,#897,#898,#899));
#901=FACE_BOUND('',#900,.T.);
#902=ADVANCED_FACE('F16',(#901),#839,.F.);
#903=CARTESIAN_POINT('',(0.,0.,26.5));
#904=DIRECTION('',(0.,0.,1.));
#905=DIRECTION('',(0.,-1.,0.));
#906=AXIS2_PLACEMENT_3D('',#903,#904,#905);
#907=PLANE('',#906);
#908=CARTESIAN_POINT('',(0.,0.,26.5));
#909=DIRECTION('',(0.,0.,1.));
#910=DIRECTION('',(0.,-1.,0.));
#911=AXIS2_PLACEMENT_3D('',#908,#909,#910);
#912=CIRCLE('',#911,11.);
#913=EDGE_CURVE('E43',#220,#265,#912,.T.);
#914=ORIENTED_EDGE('',*,*,#913,.T.);
#915=ORIENTED_EDGE('',*,*,#266,.T.);
#916=EDGE_LOOP('',(#914,#915));
#917=FACE_BOUND('',#916,.T.);
#918=ADVANCED_FACE('F534',(#917),#907,.T.);
#919=CARTESIAN_POINT('',(0.,0.,26.5));
#920=DIRECTION('',(0.,0.,-1.));
#921=DIRECTION('',(0.,1.,0.));
#922=AXIS2_PLACEMENT_3D('',#919,#920,#921);
#923=CYLINDRICAL_SURFACE('',#922,11.);
#924=ORIENTED_EDGE('',*,*,#913,.F.);
#925=ORIENTED_EDGE('',*,*,#221,.F.);
#926=DIRECTION('',(0.,0.,-1.));
#927=VECTOR('',#926,1.);
#928=CARTESIAN_POINT('',(0.,-11.,28.));
#929=LINE('',#928,#927);
#930=CARTESIAN_POINT('',(0.,-11.,28.));
#931=VERTEX_POINT('',#930);
#932=EDGE_CURVE('E373',#931,#177,#929,.T.);
#933=ORIENTED_EDGE('',*,*,#932,.F.);
#934=CARTESIAN_POINT('',(0.,0.,28.));
#935=DIRECTION('',(0.,0.,-1.));
#936=DIRECTION('',(0.,-1.,0.));
#937=AXIS2_PLACEMENT_3D('',#934,#935,#936);
#938=CIRCLE('',#937,11.);
#939=EDGE_CURVE('E364',#931,#759,#938,.T.);
#940=ORIENTED_EDGE('',*,*,#939,.T.);
#941=ORIENTED_EDGE('',*,*,#826,.F.);
#942=EDGE_CURVE('E36',#804,#800,#938,.T.);
#943=ORIENTED_EDGE('',*,*,#942,.T.);
#944=ORIENTED_EDGE('',*,*,#801,.F.);
#945=ORIENTED_EDGE('',*,*,#677,.F.);
#946=ORIENTED_EDGE('',*,*,#546,.F.);
#947=EDGE_CURVE('E762',#524,#526,#938,.T.);
#948=ORIENTED_EDGE('',*,*,#947,.T.);
#949=ORIENTED_EDGE('',*,*,#603,.F.);
#950=CARTESIAN_POINT('',(0.,11.,28.));
#951=VERTEX_POINT('',#950);
#952=EDGE_CURVE('E363',#581,#951,#938,.T.);
#953=ORIENTED_EDGE('',*,*,#952,.T.);
#954=DIRECTION('',(0.,0.,-1.));
#955=VECTOR('',#954,1.);
#956=CARTESIAN_POINT('',(0.,11.,28.));
#957=LINE('',#956,#955);
#958=EDGE_CURVE('E370',#951,#402,#957,.T.);
#959=ORIENTED_EDGE('',*,*,#958,.T.);
#960=ORIENTED_EDGE('',*,*,#403,.F.);
#961=EDGE_CURVE('E547',#357,#355,#912,.T.);
#962=ORIENTED_EDGE('',*,*,#961,.F.);
#963=ORIENTED_EDGE('',*,*,#460,.F.);
#964=ORIENTED_EDGE('',*,*,#896,.F.);
#965=ORIENTED_EDGE('',*,*,#285,.F.);
#966=EDGE_LOOP('',(#924,#925,#933,#940,#941,#943,#944,#945,#946,#948,#949,#953,#959,#960,#962,
#963,#964,#965));
#967=FACE_BOUND('',#966,.T.);
#968=ORIENTED_EDGE('',*,*,#129,.T.);
#969=EDGE_LOOP('',(#968));
#970=FACE_BOUND('',#969,.T.);
#971=ADVANCED_FACE('F532',(#967,#970),#923,.T.);
#972=ORIENTED_EDGE('',*,*,#961,.T.);
#973=ORIENTED_EDGE('',*,*,#358,.T.);
#974=EDGE_LOOP('',(#972,#973));
#975=FACE_BOUND('',#974,.T.);
#976=ADVANCED_FACE('F528',(#975),#907,.T.);
#977=CARTESIAN_POINT('',(0.,0.,28.));
#978=DIRECTION('',(0.,0.,1.));
#979=DIRECTION('',(0.,-1.,0.));
#980=AXIS2_PLACEMENT_3D('',#977,#978,#979);
#981=PLANE('',#980);
#982=ORIENTED_EDGE('',*,*,#527,.T.);
#983=ORIENTED_EDGE('',*,*,#947,.F.);
#984=EDGE_LOOP('',(#982,#983));
#985=FACE_BOUND('',#984,.T.);
#986=ADVANCED_FACE('F531',(#985),#981,.F.);
#987=ORIENTED_EDGE('',*,*,#582,.T.);
#988=DIRECTION('',(0.,1.,0.));
#989=VECTOR('',#988,1.);
#990=CARTESIAN_POINT('',(0.,11.,28.));
#991=LINE('',#990,#989);
#992=EDGE_CURVE('E367',#951,#577,#991,.T.);
#993=ORIENTED_EDGE('',*,*,#992,.F.);
#994=ORIENTED_EDGE('',*,*,#952,.F.);
#995=EDGE_LOOP('',(#987,#993,#994));
#996=FACE_BOUND('',#995,.T.);
#997=ADVANCED_FACE('F741',(#996),#981,.F.);
#998=ORIENTED_EDGE('',*,*,#760,.T.);
#999=ORIENTED_EDGE('',*,*,#939,.F.);
#1000=DIRECTION('',(0.,1.,0.));
#1001=VECTOR('',#1000,1.);
#1002=CARTESIAN_POINT('',(0.,-11.,28.));
#1003=LINE('',#1002,#1001);
#1004=EDGE_CURVE('E361',#757,#931,#1003,.T.);
#1005=ORIENTED_EDGE('',*,*,#1004,.F.);
#1006=EDGE_LOOP('',(#998,#999,#1005));
#1007=FACE_BOUND('',#1006,.T.);
#1008=ADVANCED_FACE('F735',(#1007),#981,.F.);
#1009=CARTESIAN_POINT('',(0.,-11.,28.));
#1010=DIRECTION('',(-1.,0.,0.));
#1011=DIRECTION('',(0.,-1.,0.));
#1012=AXIS2_PLACEMENT_3D('',#1009,#1010,#1011);
#1013=PLANE('',#1012);
#1014=ORIENTED_EDGE('',*,*,#773,.F.);
#1015=ORIENTED_EDGE('',*,*,#1004,.T.);
#1016=ORIENTED_EDGE('',*,*,#932,.T.);
#1017=ORIENTED_EDGE('',*,*,#178,.F.);
#1018=EDGE_LOOP('',(#1014,#1015,#1016,#1017));
#1019=FACE_BOUND('',#1018,.T.);
#1020=ADVANCED_FACE('F401',(#1019),#1013,.T.);
#1021=CARTESIAN_POINT('',(0.,11.,28.));
#1022=DIRECTION('',(-1.,0.,0.));
#1023=DIRECTION('',(0.,-1.,0.));
#1024=AXIS2_PLACEMENT_3D('',#1021,#1022,#1023);
#1025=PLANE('',#1024);
#1026=ORIENTED_EDGE('',*,*,#958,.F.);
#1027=ORIENTED_EDGE('',*,*,#992,.T.);
#1028=ORIENTED_EDGE('',*,*,#578,.F.);
#1029=ORIENTED_EDGE('',*,*,#418,.F.);
#1030=EDGE_LOOP('',(#1026,#1027,#1028,#1029));
#1031=FACE_BOUND('',#1030,.T.);
#1032=ADVANCED_FACE('F395',(#1031),#1025,.T.);
#1033=ORIENTED_EDGE('',*,*,#805,.T.);
#1034=ORIENTED_EDGE('',*,*,#942,.F.);
#1035=EDGE_LOOP('',(#1033,#1034));
#1036=FACE_BOUND('',#1035,.T.);
#1037=ADVANCED_FACE('F400',(#1036),#981,.F.);
#1038=CARTESIAN_POINT('',(0.,0.,12.));
#1039=DIRECTION('',(0.,0.,-1.));
#1040=DIRECTION('',(0.,1.,0.));
#1041=AXIS2_PLACEMENT_3D('',#1038,#1039,#1040);
#1042=CYLINDRICAL_SURFACE('',#1041,3.);
#1043=CARTESIAN_POINT('',(0.,0.,12.));
#1044=DIRECTION('',(0.,0.,1.));
#1045=DIRECTION('',(0.,-1.,0.));
#1046=AXIS2_PLACEMENT_3D('',#1043,#1044,#1045);
#1047=CIRCLE('',#1046,3.);
#1048=CARTESIAN_POINT('',(0.,-3.,12.));
#1049=VERTEX_POINT('',#1048);
#1050=EDGE_CURVE('E358',#1049,#1049,#1047,.T.);
#1051=ORIENTED_EDGE('',*,*,#1050,.T.);
#1052=EDGE_LOOP('',(#1051));
#1053=FACE_BOUND('',#1052,.T.);
#1054=ORIENTED_EDGE('',*,*,#140,.F.);
#1055=EDGE_LOOP('',(#1054));
#1056=FACE_BOUND('',#1055,.T.);
#1057=ADVANCED_FACE('F725',(#1053,#1056),#1042,.F.);
#1058=CARTESIAN_POINT('',(0.,0.,12.));
#1059=DIRECTION('',(0.,0.,1.));
#1060=DIRECTION('',(0.,-1.,0.));
#1061=AXIS2_PLACEMENT_3D('',#1058,#1059,#1060);
#1062=PLANE('',#1061);
#1063=ORIENTED_EDGE('',*,*,#1050,.F.);
#1064=EDGE_LOOP('',(#1063));
#1065=FACE_BOUND('',#1064,.T.);
#1066=ADVANCED_FACE('F727',(#1065),#1062,.F.);
#1067=CARTESIAN_POINT('',(120.989848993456,-8.47425322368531,19.9028672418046));
#1068=DIRECTION('',(0.940144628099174,0.,-0.340775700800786));
#1069=DIRECTION('',(0.,1.,0.));
#1070=AXIS2_PLACEMENT_3D('',#1067,#1068,#1069);
#1071=CIRCLE('',#1070,2.67875466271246);
#1072=CARTESIAN_POINT('',(47.2434292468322,0.,-184.999446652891));
#1073=DIRECTION('',(0.,-1.,0.));
#1074=AXIS1_PLACEMENT('',#1072,#1073);
#1075=SURFACE_OF_REVOLUTION('',#1071,#1074);
#1076=CARTESIAN_POINT('',(87.601904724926,-9.54893617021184,26.5));
#1077=CARTESIAN_POINT('',(87.6466406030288,-9.5680776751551,26.5));
#1078=CARTESIAN_POINT('',(87.691580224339,-9.58673543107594,26.5));
#1079=CARTESIAN_POINT('',(87.7818084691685,-9.62317676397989,26.5));
#1080=CARTESIAN_POINT('',(87.8270970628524,-9.64096041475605,26.5));
#1081=CARTESIAN_POINT('',(87.96337598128,-9.6931318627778,26.5));
#1082=CARTESIAN_POINT('',(88.0548130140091,-9.72635434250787,26.5));
#1083=CARTESIAN_POINT('',(88.2382563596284,-9.79012691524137,26.5));
#1084=CARTESIAN_POINT('',(88.3302596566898,-9.82068575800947,26.5));
#1085=CARTESIAN_POINT('',(88.514961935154,-9.87964899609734,26.5));
#1086=CARTESIAN_POINT('',(88.607660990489,-9.90805315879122,26.5));
#1087=CARTESIAN_POINT('',(88.8863773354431,-9.99043080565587,26.5));
#1088=CARTESIAN_POINT('',(89.0732134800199,-10.0416372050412,26.5));
#1089=CARTESIAN_POINT('',(89.4483301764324,-10.1382884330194,26.5));
#1090=CARTESIAN_POINT('',(89.636610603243,-10.1837337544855,26.5));
#1091=CARTESIAN_POINT('',(90.0132130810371,-10.2696575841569,26.5));
#1092=CARTESIAN_POINT('',(90.2015292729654,-10.3101618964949,26.5));
#1093=CARTESIAN_POINT('',(90.5790796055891,-10.387209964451,26.5));
#1094=CARTESIAN_POINT('',(90.7683142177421,-10.4237513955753,26.5));
#1095=CARTESIAN_POINT('',(91.1474989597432,-10.4933553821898,26.5));
#1096=CARTESIAN_POINT('',(91.3374493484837,-10.5264165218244,26.5));
#1097=CARTESIAN_POINT('',(91.7178849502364,-10.5894080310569,26.5));
#1098=CARTESIAN_POINT('',(91.9083702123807,-10.6193381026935,26.5));
#1099=CARTESIAN_POINT('',(92.3307179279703,-10.6824552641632,26.5));
#1100=CARTESIAN_POINT('',(92.5626820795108,-10.7149616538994,26.5));
#1101=CARTESIAN_POINT('',(93.0270500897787,-10.7760965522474,26.5));
#1102=CARTESIAN_POINT('',(93.2594538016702,-10.8047261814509,26.5));
#1103=CARTESIAN_POINT('',(93.7246419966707,-10.8583639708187,26.5));
#1104=CARTESIAN_POINT('',(93.9574264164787,-10.8833726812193,26.5));
#1105=CARTESIAN_POINT('',(94.4233246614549,-10.9299465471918,26.5));
#1106=CARTESIAN_POINT('',(94.6564384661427,-10.9515119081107,26.5));
#1107=CARTESIAN_POINT('',(95.1244619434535,-10.9914452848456,26.5));
#1108=CARTESIAN_POINT('',(95.3593734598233,-11.0097916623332,26.5));
#1109=CARTESIAN_POINT('',(95.8294484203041,-11.0431842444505,26.5));
#1110=CARTESIAN_POINT('',(96.0646118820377,-11.0582302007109,26.5));
#1111=CARTESIAN_POINT('',(96.5351523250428,-11.0850508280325,26.5));
#1112=CARTESIAN_POINT('',(96.7705293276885,-11.0968251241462,26.5));
#1113=CARTESIAN_POINT('',(97.2414606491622,-11.1170841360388,26.5));
#1114=CARTESIAN_POINT('',(97.4770149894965,-11.1255683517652,26.5));
#1115=CARTESIAN_POINT('',(97.7126175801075,-11.1323977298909,26.5));
#1116=B_SPLINE_CURVE_WITH_KNOTS('',3,(#1076,#1077,#1078,#1079,#1080,#1081,#1082,#1083,#1084,
#1085,#1086,#1087,#1088,#1089,#1090,#1091,#1092,#1093,#1094,#1095,#1096,#1097,#1098,#1099,#1100,
#1101,#1102,#1103,#1104,#1105,#1106,#1107,#1108,#1109,#1110,#1111,#1112,#1113,#1114,#1115),
.UNSPECIFIED.,.F.,.F.,(4,2,2,2,2,2,2,2,2,2,2,2,2,2,2,2,2,2,2,4),(0.,0.145969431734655,
0.29192651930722,0.583731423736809,0.87453850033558,1.16537692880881,1.7464217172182,
2.32741676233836,2.9052343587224,3.48338907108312,4.0617780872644,4.64022209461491,
5.34287747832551,6.0453293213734,6.74767430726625,7.44997739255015,8.15683422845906,
8.86374423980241,9.57073523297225,10.2778336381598),.UNSPECIFIED.);
#1117=CARTESIAN_POINT('',(88.9053338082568,-9.99445058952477,26.5));
#1118=VERTEX_POINT('',#1117);
#1119=CARTESIAN_POINT('',(94.5949482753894,-10.9453683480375,26.5));
#1120=VERTEX_POINT('',#1119);
#1121=EDGE_CURVE('E345',#1118,#1120,#1116,.T.);
#1122=ORIENTED_EDGE('',*,*,#1121,.T.);
#1123=CARTESIAN_POINT('',(98.9605693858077,-9.54893617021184,24.0128972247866));
#1124=CARTESIAN_POINT('',(98.8515883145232,-9.61125288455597,24.0679927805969));
#1125=CARTESIAN_POINT('',(98.7422657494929,-9.67129756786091,24.1249341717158));
#1126=CARTESIAN_POINT('',(98.5232269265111,-9.78685393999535,24.2418321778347));
#1127=CARTESIAN_POINT('',(98.4135121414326,-9.84237568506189,24.3017815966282));
#1128=CARTESIAN_POINT('',(98.1936195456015,-9.9491129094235,24.4241981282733));
#1129=CARTESIAN_POINT('',(98.0834425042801,-10.0003337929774,24.4866619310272));
#1130=CARTESIAN_POINT('',(97.8625558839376,-10.0986490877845,24.613680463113));
#1131=CARTESIAN_POINT('',(97.7518466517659,-10.1457458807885,24.6782339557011));
#1132=CARTESIAN_POINT('',(97.5298281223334,-10.2359582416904,24.8090281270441));
#1133=CARTESIAN_POINT('',(97.4185188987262,-10.2790742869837,24.8752686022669));
#1134=CARTESIAN_POINT('',(97.1973636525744,-10.3606528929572,25.0077619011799));
#1135=CARTESIAN_POINT('',(97.0875299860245,-10.3991882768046,25.0739906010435));
#1136=CARTESIAN_POINT('',(96.867119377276,-10.4726312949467,25.2073144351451));
#1137=CARTESIAN_POINT('',(96.7565421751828,-10.5075375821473,25.2744098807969));
#1138=CARTESIAN_POINT('',(96.5345313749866,-10.5737904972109,25.4090531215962));
#1139=CARTESIAN_POINT('',(96.4230974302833,-10.6051355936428,25.4766010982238));
#1140=CARTESIAN_POINT('',(96.1992179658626,-10.6643159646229,25.6116735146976));
#1141=CARTESIAN_POINT('',(96.0867720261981,-10.6921497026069,25.6791979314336));
#1142=CARTESIAN_POINT('',(95.8606455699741,-10.7443392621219,25.813649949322));
#1143=CARTESIAN_POINT('',(95.7469645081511,-10.7686934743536,25.8805772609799));
#1144=CARTESIAN_POINT('',(95.5493709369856,-10.8077408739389,25.9949552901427));
#1145=CARTESIAN_POINT('',(95.4658092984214,-10.8232558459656,26.0427323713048));
#1146=CARTESIAN_POINT('',(95.2977861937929,-10.8524298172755,26.1371541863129));
#1147=CARTESIAN_POINT('',(95.2133252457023,-10.8660898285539,26.1837995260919));
#1148=CARTESIAN_POINT('',(95.0433662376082,-10.8915286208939,26.2754555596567));
#1149=CARTESIAN_POINT('',(94.9578695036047,-10.9033095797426,26.3204680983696));
#1150=CARTESIAN_POINT('',(94.7856358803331,-10.9249560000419,26.4082404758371));
#1151=CARTESIAN_POINT('',(94.6989009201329,-10.9348241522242,26.4510034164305));
#1152=CARTESIAN_POINT('',(94.5228542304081,-10.9527020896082,26.5340177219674));
#1153=CARTESIAN_POINT('',(94.4335246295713,-10.9606901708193,26.5742361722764));
#1154=CARTESIAN_POINT('',(94.252938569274,-10.9745746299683,26.6506498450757));
#1155=CARTESIAN_POINT('',(94.1616812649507,-10.9804700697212,26.6868432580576));
#1156=CARTESIAN_POINT('',(93.9768376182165,-10.9900505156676,26.7541263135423));
#1157=CARTESIAN_POINT('',(93.8832449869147,-10.993728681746,26.7851999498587));
#1158=CARTESIAN_POINT('',(93.7410432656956,-10.9974619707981,26.8271246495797));
#1159=CARTESIAN_POINT('',(93.6931540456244,-10.9984092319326,26.8403600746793));
#1160=CARTESIAN_POINT('',(93.5969122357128,-10.9996784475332,26.8651070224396));
#1161=CARTESIAN_POINT('',(93.5485595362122,-11.0000002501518,26.8766181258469));
#1162=CARTESIAN_POINT('',(93.5,-10.9999999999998,26.8872131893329));
#1163=B_SPLINE_CURVE_WITH_KNOTS('',3,(#1123,#1124,#1125,#1126,#1127,#1128,#1129,#1130,#1131,
#1132,#1133,#1134,#1135,#1136,#1137,#1138,#1139,#1140,#1141,#1142,#1143,#1144,#1145,#1146,#1147,
#1148,#1149,#1150,#1151,#1152,#1153,#1154,#1155,#1156,#1157,#1158,#1159,#1160,#1161,#1162),
.UNSPECIFIED.,.F.,.F.,(4,2,2,2,2,2,2,2,2,2,2,2,2,2,2,2,2,2,2,4),(0.,0.411233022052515,
0.821525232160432,1.23129392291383,1.64082438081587,2.05030566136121,2.45201061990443,
2.8538641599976,3.25588986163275,3.65809088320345,4.06047732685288,4.35294815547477,
4.64525877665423,4.93722811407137,5.22878371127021,5.52355595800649,5.81846019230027,
6.11426958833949,6.26331784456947,6.41240228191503),.UNSPECIFIED.);
#1164=CARTESIAN_POINT('',(93.5,-11.,26.8872131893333));
#1165=VERTEX_POINT('',#1164);
#1166=EDGE_CURVE('E273',#1120,#1165,#1163,.T.);
#1167=ORIENTED_EDGE('',*,*,#1166,.T.);
#1168=CARTESIAN_POINT('',(93.5,-11.,26.8872131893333));
#1169=CARTESIAN_POINT('',(93.5,-11.0127787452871,26.9242320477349));
#1170=CARTESIAN_POINT('',(93.5,-11.0247761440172,26.9615212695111));
#1171=CARTESIAN_POINT('',(93.5,-11.0471519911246,27.0364403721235));
#1172=CARTESIAN_POINT('',(93.5,-11.0575359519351,27.0740686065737));
#1173=CARTESIAN_POINT('',(93.5,-11.0767014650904,27.1496593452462));
#1174=CARTESIAN_POINT('',(93.5,-11.0854857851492,27.1876211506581));
#1175=CARTESIAN_POINT('',(93.5,-11.1174827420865,27.34034800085));
#1176=CARTESIAN_POINT('',(93.5,-11.1343057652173,27.4564772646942));
#1177=CARTESIAN_POINT('',(93.5,-11.1437941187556,27.5733366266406));
#1178=B_SPLINE_CURVE_WITH_KNOTS('',3,(#1168,#1169,#1170,#1171,#1172,#1173,#1174,#1175,#1176,
#1177),.UNSPECIFIED.,.F.,.F.,(4,2,2,2,4),(0.,0.117479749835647,0.234548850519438,
0.351413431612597,0.702620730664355),.UNSPECIFIED.);
#1179=CARTESIAN_POINT('',(93.5,-11.1437941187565,27.5733366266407));
#1180=VERTEX_POINT('',#1179);
#1181=EDGE_CURVE('E236',#1165,#1180,#1178,.T.);
#1182=ORIENTED_EDGE('',*,*,#1181,.T.);
#1183=CARTESIAN_POINT('',(47.2434292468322,-11.1437941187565,-184.999446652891));
#1184=DIRECTION('',(0.,-1.,0.));
#1185=DIRECTION('',(1.,0.,0.));
#1186=AXIS2_PLACEMENT_3D('',#1183,#1184,#1185);
#1187=CIRCLE('',#1186,217.547370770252);
#1188=EDGE_CURVE('E353',#1180,#162,#1187,.T.);
#1189=ORIENTED_EDGE('',*,*,#1188,.T.);
#1190=ORIENTED_EDGE('',*,*,#299,.T.);
#1191=ORIENTED_EDGE('',*,*,#105,.F.);
#1192=CARTESIAN_POINT('',(88.0394306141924,-9.54893617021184,26.4160417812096));
#1193=CARTESIAN_POINT('',(88.0865475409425,-9.57588012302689,26.4189684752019));
#1194=CARTESIAN_POINT('',(88.1338481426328,-9.60246616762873,26.4222237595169));
#1195=CARTESIAN_POINT('',(88.2287711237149,-9.6548994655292,26.4293504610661));
#1196=CARTESIAN_POINT('',(88.2763932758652,-9.68074718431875,26.433221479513));
#1197=CARTESIAN_POINT('',(88.3719599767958,-9.73170782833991,26.4415412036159));
#1198=CARTESIAN_POINT('',(88.4199044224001,-9.75682097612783,26.4459897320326));
#1199=CARTESIAN_POINT('',(88.5161154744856,-9.80631539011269,26.4554275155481));
#1200=CARTESIAN_POINT('',(88.5643820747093,-9.83069667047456,26.4604167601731));
#1201=CARTESIAN_POINT('',(88.6612411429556,-9.87873149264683,26.4709004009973));
#1202=CARTESIAN_POINT('',(88.7098337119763,-9.90238479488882,26.4763949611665));
#1203=CARTESIAN_POINT('',(88.8073475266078,-9.94896650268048,26.4878544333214));
#1204=CARTESIAN_POINT('',(88.8562689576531,-9.97189444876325,26.4938196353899));
#1205=CARTESIAN_POINT('',(88.9053338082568,-9.99445058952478,26.5));
#1206=B_SPLINE_CURVE_WITH_KNOTS('',3,(#1192,#1193,#1194,#1195,#1196,#1197,#1198,#1199,#1200,
#1201,#1202,#1203,#1204,#1205),.UNSPECIFIED.,.F.,.F.,(4,2,2,2,2,2,4),(0.,0.163064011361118,
0.32602283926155,0.488931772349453,0.651837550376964,0.814796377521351,0.977856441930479),.UNSPECIFIED.);
#1207=EDGE_CURVE('E661',#95,#1118,#1206,.T.);
#1208=ORIENTED_EDGE('',*,*,#1207,.T.);
#1209=EDGE_LOOP('',(#1122,#1167,#1182,#1189,#1190,#1191,#1208));
#1210=FACE_BOUND('',#1209,.T.);
#1211=ADVANCED_FACE('F621',(#1210),#1075,.T.);
#1212=CARTESIAN_POINT('',(120.86622545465,-9.54999999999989,19.5618100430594));
#1213=DIRECTION('',(0.940144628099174,0.,-0.340775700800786));
#1214=DIRECTION('',(0.,1.,0.));
#1215=AXIS2_PLACEMENT_3D('',#1212,#1213,#1214);
#1216=CIRCLE('',#1215,1.6);
#1217=CARTESIAN_POINT('',(47.2434292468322,0.,-184.999446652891));
#1218=DIRECTION('',(0.,-1.,0.));
#1219=AXIS1_PLACEMENT('',#1217,#1218);
#1220=SURFACE_OF_REVOLUTION('',#1216,#1219);
#1221=ORIENTED_EDGE('',*,*,#1188,.F.);
#1222=CARTESIAN_POINT('',(93.5,-11.1437941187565,27.5733366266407));
#1223=CARTESIAN_POINT('',(93.5,-11.1375132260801,27.6461630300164));
#1224=CARTESIAN_POINT('',(93.5,-11.1264600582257,27.7184865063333));
#1225=CARTESIAN_POINT('',(93.5,-11.1055098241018,27.8134739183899));
#1226=CARTESIAN_POINT('',(93.5,-11.0997631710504,27.8370707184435));
#1227=CARTESIAN_POINT('',(93.5,-11.087232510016,27.8840366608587));
#1228=CARTESIAN_POINT('',(93.5,-11.0804465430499,27.9074052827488));
#1229=CARTESIAN_POINT('',(93.5,-11.0658293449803,27.9539115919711));
#1230=CARTESIAN_POINT('',(93.5,-11.0579942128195,27.9770480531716));
#1231=CARTESIAN_POINT('',(93.5,-11.0496525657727,27.9999999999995));
#1232=B_SPLINE_CURVE_WITH_KNOTS('',3,(#1222,#1223,#1224,#1225,#1226,#1227,#1228,#1229,#1230,
#1231),.UNSPECIFIED.,.F.,.F.,(4,2,2,2,4),(0.,0.218933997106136,0.291772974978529,
0.364750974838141,0.438008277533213),.UNSPECIFIED.);
#1233=CARTESIAN_POINT('',(93.5,-11.0496525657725,28.));
#1234=VERTEX_POINT('',#1233);
#1235=EDGE_CURVE('E209',#1180,#1234,#1232,.T.);
#1236=ORIENTED_EDGE('',*,*,#1235,.T.);
#1237=CARTESIAN_POINT('',(93.5,-11.0496525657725,28.));
#1238=CARTESIAN_POINT('',(93.6028303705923,-11.0415342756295,28.));
#1239=CARTESIAN_POINT('',(93.705617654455,-11.0328561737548,28.));
#1240=CARTESIAN_POINT('',(93.9113247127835,-11.014272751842,28.));
#1241=CARTESIAN_POINT('',(94.014244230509,-11.0043645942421,28.));
#1242=CARTESIAN_POINT('',(94.2201209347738,-10.9832333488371,28.));
#1243=CARTESIAN_POINT('',(94.3230779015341,-10.9720081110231,28.));
#1244=CARTESIAN_POINT('',(94.5289319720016,-10.9481359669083,28.));
#1245=CARTESIAN_POINT('',(94.6318289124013,-10.9354876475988,28.));
#1246=CARTESIAN_POINT('',(94.8374633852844,-10.9086433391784,28.));
#1247=CARTESIAN_POINT('',(94.9402008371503,-10.8944467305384,28.));
#1248=CARTESIAN_POINT('',(95.1525789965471,-10.8633023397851,28.));
#1249=CARTESIAN_POINT('',(95.2622018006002,-10.8462317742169,28.));
#1250=CARTESIAN_POINT('',(95.4810387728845,-10.8099065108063,28.));
#1251=CARTESIAN_POINT('',(95.5902530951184,-10.7906527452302,28.));
#1252=CARTESIAN_POINT('',(95.8081419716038,-10.7496538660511,28.));
#1253=CARTESIAN_POINT('',(95.9168168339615,-10.7279104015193,28.));
#1254=CARTESIAN_POINT('',(96.1334730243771,-10.681519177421,28.));
#1255=CARTESIAN_POINT('',(96.2414547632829,-10.6568733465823,28.));
#1256=CARTESIAN_POINT('',(96.4565497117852,-10.6041021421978,28.));
#1257=CARTESIAN_POINT('',(96.5636631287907,-10.5759776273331,28.));
#1258=CARTESIAN_POINT('',(96.7208406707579,-10.5312836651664,28.));
#1259=CARTESIAN_POINT('',(96.7713811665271,-10.5163838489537,28.));
#1260=CARTESIAN_POINT('',(96.8721258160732,-10.4854798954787,28.));
#1261=CARTESIAN_POINT('',(96.9223299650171,-10.4694757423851,28.));
#1262=CARTESIAN_POINT('',(97.0223234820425,-10.4362138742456,28.));
#1263=CARTESIAN_POINT('',(97.0721128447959,-10.4189561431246,28.));
#1264=CARTESIAN_POINT('',(97.1704687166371,-10.383250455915,28.));
#1265=CARTESIAN_POINT('',(97.2190425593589,-10.3648228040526,27.9999999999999));
#1266=CARTESIAN_POINT('',(97.3155411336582,-10.3263258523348,28.0000000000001));
#1267=CARTESIAN_POINT('',(97.3634658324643,-10.3062564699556,28.0000000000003));
#1268=CARTESIAN_POINT('',(97.4584809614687,-10.264154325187,27.9999999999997));
#1269=CARTESIAN_POINT('',(97.5055709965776,-10.2421206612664,27.9999999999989));
#1270=CARTESIAN_POINT('',(97.5815081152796,-10.2041891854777,27.9999999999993));
#1271=CARTESIAN_POINT('',(97.6107115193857,-10.189004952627,27.9999999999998));
#1272=CARTESIAN_POINT('',(97.6685034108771,-10.1575450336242,28.0000000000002));
#1273=CARTESIAN_POINT('',(97.6970922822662,-10.1412700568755,28.0000000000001));
#1274=CARTESIAN_POINT('',(97.7534658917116,-10.1074677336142,28.));
#1275=CARTESIAN_POINT('',(97.7812517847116,-10.0899423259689,28.));
#1276=CARTESIAN_POINT('',(97.8361791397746,-10.0531573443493,28.));
#1277=CARTESIAN_POINT('',(97.8633076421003,-10.0338782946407,28.));
#1278=CARTESIAN_POINT('',(97.916217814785,-9.99345746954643,28.));
#1279=CARTESIAN_POINT('',(97.9419977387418,-9.97231336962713,28.));
#1280=CARTESIAN_POINT('',(97.979271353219,-9.93887561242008,28.));
#1281=CARTESIAN_POINT('',(97.9915011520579,-9.9274020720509,28.));
#1282=CARTESIAN_POINT('',(98.0153623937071,-9.90383435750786,28.));
#1283=CARTESIAN_POINT('',(98.0269934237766,-9.891739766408,28.));
#1284=CARTESIAN_POINT('',(98.0382672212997,-9.87931034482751,28.));
#1285=B_SPLINE_CURVE_WITH_KNOTS('',3,(#1237,#1238,#1239,#1240,#1241,#1242,#1243,#1244,#1245,
#1246,#1247,#1248,#1249,#1250,#1251,#1252,#1253,#1254,#1255,#1256,#1257,#1258,#1259,#1260,#1261,
#1262,#1263,#1264,#1265,#1266,#1267,#1268,#1269,#1270,#1271,#1272,#1273,#1274,#1275,#1276,#1277,
#1278,#1279,#1280,#1281,#1282,#1283,#1284),.UNSPECIFIED.,.F.,.F.,(4,2,2,2,2,2,2,2,2,2,2,2,2,2,2,
2,2,2,2,2,2,2,2,4),(0.,0.309451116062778,0.619629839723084,0.930322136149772,1.24132569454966,
1.55245415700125,1.8852662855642,2.21793682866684,2.55038828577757,2.88262005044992,
3.21476996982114,3.37283312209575,3.53089854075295,3.68896598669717,3.8447961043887,
4.00063405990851,4.15654391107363,4.25526989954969,4.35393228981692,4.45244489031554,
4.55222994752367,4.65214117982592,4.70242936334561,4.75275175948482),.UNSPECIFIED.);
#1286=CARTESIAN_POINT('',(94.3985532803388,-10.9632386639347,28.));
#1287=VERTEX_POINT('',#1286);
#1288=EDGE_CURVE('E679',#1234,#1287,#1285,.T.);
#1289=ORIENTED_EDGE('',*,*,#1288,.T.);
#1290=CARTESIAN_POINT('',(94.3985532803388,-10.9632386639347,28.));
#1291=CARTESIAN_POINT('',(94.4699849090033,-10.957384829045,27.9954843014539));
#1292=CARTESIAN_POINT('',(94.5414127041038,-10.9508270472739,27.9919674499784));
#1293=CARTESIAN_POINT('',(94.6840632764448,-10.936321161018,27.9865828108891));
#1294=CARTESIAN_POINT('',(94.7552861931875,-10.9283755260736,27.9847121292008));
#1295=CARTESIAN_POINT('',(94.8975160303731,-10.9110988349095,27.9822589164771));
#1296=CARTESIAN_POINT('',(94.9685230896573,-10.9017690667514,27.9816751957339));
#1297=CARTESIAN_POINT('',(95.1103175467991,-10.8817279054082,27.9814724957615));
#1298=CARTESIAN_POINT('',(95.1811050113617,-10.8710169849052,27.9818531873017));
#1299=CARTESIAN_POINT('',(95.3224290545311,-10.8482198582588,27.983292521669));
#1300=CARTESIAN_POINT('',(95.3929657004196,-10.8361340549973,27.984350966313));
#1301=CARTESIAN_POINT('',(95.5338219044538,-10.8105825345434,27.9868957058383));
#1302=CARTESIAN_POINT('',(95.6041413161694,-10.7971160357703,27.9883822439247));
#1303=CARTESIAN_POINT('',(95.744567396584,-10.7687999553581,27.9915627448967));
#1304=CARTESIAN_POINT('',(95.8146737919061,-10.7539490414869,27.993256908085));
#1305=CARTESIAN_POINT('',(95.9546771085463,-10.7228591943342,27.9966632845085));
#1306=CARTESIAN_POINT('',(96.02457361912,-10.706618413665,27.99837551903));
#1307=CARTESIAN_POINT('',(96.0943064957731,-10.6896947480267,28.));
#1308=B_SPLINE_CURVE_WITH_KNOTS('',3,(#1290,#1291,#1292,#1293,#1294,#1295,#1296,#1297,#1298,
#1299,#1300,#1301,#1302,#1303,#1304,#1305,#1306,#1307),.UNSPECIFIED.,.F.,.F.,(4,2,2,2,2,2,2,2,
4),(0.,0.215415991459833,0.430452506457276,0.645290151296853,0.860054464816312,1.07475600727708,
1.28957976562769,1.50461242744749,1.71993548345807),.UNSPECIFIED.);
#1309=CARTESIAN_POINT('',(96.0943064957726,-10.6896947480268,28.));
#1310=VERTEX_POINT('',#1309);
#1311=EDGE_CURVE('E305',#1287,#1310,#1308,.T.);
#1312=ORIENTED_EDGE('',*,*,#1311,.T.);
#1313=CARTESIAN_POINT('',(97.4675566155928,-10.2595562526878,28.));
#1314=VERTEX_POINT('',#1313);
#1315=EDGE_CURVE('E680',#1310,#1314,#1285,.T.);
#1316=ORIENTED_EDGE('',*,*,#1315,.T.);
#1317=CARTESIAN_POINT('',(97.4675566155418,-10.2595562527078,28.0000000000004));
#1318=CARTESIAN_POINT('',(97.5169079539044,-10.2404713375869,27.9980651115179));
#1319=CARTESIAN_POINT('',(97.566112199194,-10.2210336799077,27.9958404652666));
#1320=CARTESIAN_POINT('',(97.6641692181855,-10.1814776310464,27.990763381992));
#1321=CARTESIAN_POINT('',(97.7130222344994,-10.1613597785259,27.987911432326));
#1322=CARTESIAN_POINT('',(97.8103757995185,-10.1204469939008,27.9815299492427));
#1323=CARTESIAN_POINT('',(97.858876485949,-10.0996523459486,27.9780006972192));
#1324=CARTESIAN_POINT('',(97.9555264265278,-10.0573886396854,27.9702126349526));
#1325=CARTESIAN_POINT('',(98.0036756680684,-10.0359195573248,27.9659537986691));
#1326=CARTESIAN_POINT('',(98.0996166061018,-9.99231226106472,27.9566528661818));
#1327=CARTESIAN_POINT('',(98.1474081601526,-9.97017379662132,27.951610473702));
#1328=CARTESIAN_POINT('',(98.2426293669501,-9.92523258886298,27.9406852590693));
#1329=CARTESIAN_POINT('',(98.2900586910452,-9.90242931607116,27.9348017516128));
#1330=CARTESIAN_POINT('',(98.3372747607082,-9.87931034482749,27.9284725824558));
#1331=B_SPLINE_CURVE_WITH_KNOTS('',3,(#1317,#1318,#1319,#1320,#1321,#1322,#1323,#1324,#1325,
#1326,#1327,#1328,#1329,#1330),.UNSPECIFIED.,.F.,.F.,(4,2,2,2,2,2,4),(0.,0.158843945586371,
0.317564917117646,0.476220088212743,0.63488092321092,0.793601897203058,0.952452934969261),.UNSPECIFIED.);
#1332=CARTESIAN_POINT('',(98.3372747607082,-9.87931034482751,27.9284725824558));
#1333=VERTEX_POINT('',#1332);
#1334=EDGE_CURVE('E299',#1314,#1333,#1331,.T.);
#1335=ORIENTED_EDGE('',*,*,#1334,.T.);
#1336=CARTESIAN_POINT('',(47.2434292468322,-9.87931034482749,-184.999446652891));
#1337=DIRECTION('',(0.,-1.,0.));
#1338=DIRECTION('',(1.,0.,0.));
#1339=AXIS2_PLACEMENT_3D('',#1336,#1337,#1338);
#1340=CIRCLE('',#1339,218.972326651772);
#1341=EDGE_CURVE('E351',#1333,#685,#1340,.T.);
#1342=ORIENTED_EDGE('',*,*,#1341,.T.);
#1343=ORIENTED_EDGE('',*,*,#781,.T.);
#1344=EDGE_LOOP('',(#1221,#1236,#1289,#1312,#1316,#1335,#1342,#1343));
#1345=FACE_BOUND('',#1344,.T.);
#1346=ADVANCED_FACE('F243',(#1345),#1220,.T.);
#1347=CARTESIAN_POINT('',(105.392766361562,0.,-23.1269421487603));
#1348=DIRECTION('',(0.940144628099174,0.,-0.340775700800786));
#1349=DIRECTION('',(0.,1.,0.));
#1350=AXIS2_PLACEMENT_3D('',#1347,#1348,#1349);
#1351=CIRCLE('',#1350,48.0000000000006);
#1352=CARTESIAN_POINT('',(47.2434292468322,0.,-184.999446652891));
#1353=DIRECTION('',(0.,-1.,0.));
#1354=AXIS1_PLACEMENT('',#1352,#1353);
#1355=SURFACE_OF_REVOLUTION('',#1351,#1354);
#1356=ORIENTED_EDGE('',*,*,#1341,.F.);
#1357=CARTESIAN_POINT('',(98.3372747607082,-9.87931034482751,27.9284725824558));
#1358=CARTESIAN_POINT('',(98.6112552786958,-9.74520228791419,27.8917302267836));
#1359=CARTESIAN_POINT('',(98.8799065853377,-9.59949129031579,27.8576368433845));
#1360=CARTESIAN_POINT('',(99.404580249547,-9.28596228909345,27.794445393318));
#1361=CARTESIAN_POINT('',(99.6606033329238,-9.1181455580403,27.7653470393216));
#1362=CARTESIAN_POINT('',(100.157843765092,-8.76165908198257,27.7118644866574));
#1363=CARTESIAN_POINT('',(100.399075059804,-8.57300946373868,27.6874757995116));
#1364=CARTESIAN_POINT('',(100.865189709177,-8.17604276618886,27.6429790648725));
#1365=CARTESIAN_POINT('',(101.090073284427,-7.96772595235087,27.6228709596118));
#1366=CARTESIAN_POINT('',(101.521920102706,-7.53277928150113,27.5864843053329));
#1367=CARTESIAN_POINT('',(101.728874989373,-7.3061409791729,27.5702075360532));
#1368=CARTESIAN_POINT('',(102.123221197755,-6.83623697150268,27.5410234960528));
#1369=CARTESIAN_POINT('',(102.310612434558,-6.59297119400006,27.5281162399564));
#1370=CARTESIAN_POINT('',(102.664436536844,-6.0915711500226,27.5051958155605));
#1371=CARTESIAN_POINT('',(102.830872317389,-5.83343895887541,27.4951822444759));
#1372=CARTESIAN_POINT('',(103.141611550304,-5.30410367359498,27.4775846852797));
#1373=CARTESIAN_POINT('',(103.285915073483,-5.03290062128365,27.4700006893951));
#1374=CARTESIAN_POINT('',(103.551648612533,-4.47872739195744,27.456818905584));
#1375=CARTESIAN_POINT('',(103.673027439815,-4.19573256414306,27.4512255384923));
#1376=CARTESIAN_POINT('',(103.891647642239,-3.62054140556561,27.4416665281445));
#1377=CARTESIAN_POINT('',(103.98888894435,-3.3283450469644,27.4377008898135));
#1378=CARTESIAN_POINT('',(104.158554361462,-2.73677173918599,27.4310784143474));
#1379=CARTESIAN_POINT('',(104.230974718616,-2.43739371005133,27.428421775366));
#1380=CARTESIAN_POINT('',(104.350464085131,-1.83361309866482,27.42417391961));
#1381=CARTESIAN_POINT('',(104.39753305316,-1.52921050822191,27.4225827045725));
#1382=CARTESIAN_POINT('',(104.466109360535,-0.916426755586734,27.4202996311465));
#1383=CARTESIAN_POINT('',(104.487524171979,-0.608035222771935,27.4196110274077));
#1384=CARTESIAN_POINT('',(104.504331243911,0.00945743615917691,27.4190687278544));
#1385=CARTESIAN_POINT('',(104.499723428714,0.318558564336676,27.4192150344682));
#1386=CARTESIAN_POINT('',(104.464518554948,0.93526522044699,27.4203587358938));
#1387=CARTESIAN_POINT('',(104.433922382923,1.2428707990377,27.4213561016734));
#1388=CARTESIAN_POINT('',(104.346959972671,1.85441249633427,27.4243087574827));
#1389=CARTESIAN_POINT('',(104.290593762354,2.15834861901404,27.4262640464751));
#1390=CARTESIAN_POINT('',(104.152444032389,2.76060758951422,27.4313284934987));
#1391=CARTESIAN_POINT('',(104.070642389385,3.05892627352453,27.4344384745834));
#1392=CARTESIAN_POINT('',(103.882220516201,3.64760308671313,27.442087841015));
#1393=CARTESIAN_POINT('',(103.77560016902,3.93796117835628,27.4466272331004));
#1394=CARTESIAN_POINT('',(103.538300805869,4.50866105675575,27.4574833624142));
#1395=CARTESIAN_POINT('',(103.407620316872,4.78900222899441,27.4638002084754));
#1396=CARTESIAN_POINT('',(103.123153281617,5.33763999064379,27.4786184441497));
#1397=CARTESIAN_POINT('',(102.96936712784,5.60593678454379,27.4871197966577));
#1398=CARTESIAN_POINT('',(102.639986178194,6.12828537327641,27.5067488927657));
#1399=CARTESIAN_POINT('',(102.464415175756,6.38235227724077,27.5178737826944));
#1400=CARTESIAN_POINT('',(102.09262510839,6.87473399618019,27.5432325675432));
#1401=CARTESIAN_POINT('',(101.896405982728,7.11304876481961,27.5574664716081));
#1402=CARTESIAN_POINT('',(101.484856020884,7.5721225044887,27.5895230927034));
#1403=CARTESIAN_POINT('',(101.269533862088,7.79288936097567,27.6073441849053));
#1404=CARTESIAN_POINT('',(100.821416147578,8.21533439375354,27.6470386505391));
#1405=CARTESIAN_POINT('',(100.588625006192,8.41701736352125,27.6689110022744));
#1406=CARTESIAN_POINT('',(100.036235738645,8.85640977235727,27.7242694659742));
#1407=CARTESIAN_POINT('',(99.7112565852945,9.08724753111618,27.7592789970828));
#1408=CARTESIAN_POINT('',(99.2074653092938,9.40554757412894,27.8179830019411));
#1409=CARTESIAN_POINT('',(99.0369170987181,9.50693792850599,27.8385690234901));
#1410=CARTESIAN_POINT('',(98.6907631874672,9.70027102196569,27.881889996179));
#1411=CARTESIAN_POINT('',(98.5151564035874,9.79221171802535,27.9046254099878));
#1412=CARTESIAN_POINT('',(98.3372747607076,9.87931034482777,27.9284725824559));
#1413=B_SPLINE_CURVE_WITH_KNOTS('',3,(#1357,#1358,#1359,#1360,#1361,#1362,#1363,#1364,#1365,
#1366,#1367,#1368,#1369,#1370,#1371,#1372,#1373,#1374,#1375,#1376,#1377,#1378,#1379,#1380,#1381,
#1382,#1383,#1384,#1385,#1386,#1387,#1388,#1389,#1390,#1391,#1392,#1393,#1394,#1395,#1396,#1397,
#1398,#1399,#1400,#1401,#1402,#1403,#1404,#1405,#1406,#1407,#1408,#1409,#1410,#1411,#1412),
.UNSPECIFIED.,.F.,.F.,(4,2,2,2,2,2,2,2,2,2,2,2,2,2,2,2,2,2,2,2,2,2,2,2,2,2,2,4),(0.,
0.921459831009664,1.84286663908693,2.76339093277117,3.68390280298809,4.60484143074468,
5.5257840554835,6.44659842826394,7.36740985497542,8.29025366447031,9.21310026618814,
10.1360865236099,11.0590742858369,11.9853810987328,12.9116906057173,13.8379685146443,
14.7642454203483,15.6911838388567,16.6181266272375,17.5451261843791,18.4721099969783,
19.398090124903,20.3240729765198,21.2496373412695,22.1749686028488,23.3726920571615,
23.9708670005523,24.5691709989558),.UNSPECIFIED.);
#1414=CARTESIAN_POINT('',(98.3372747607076,9.87931034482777,27.9284725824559));
#1415=VERTEX_POINT('',#1414);
#1416=EDGE_CURVE('E293',#1333,#1415,#1413,.T.);
#1417=ORIENTED_EDGE('',*,*,#1416,.T.);
#1418=CARTESIAN_POINT('',(47.2434292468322,9.87931034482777,-184.999446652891));
#1419=DIRECTION('',(0.,-1.,0.));
#1420=DIRECTION('',(1.,0.,0.));
#1421=AXIS2_PLACEMENT_3D('',#1418,#1419,#1420);
#1422=CIRCLE('',#1421,218.972326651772);
#1423=EDGE_CURVE('E349',#1415,#554,#1422,.T.);
#1424=ORIENTED_EDGE('',*,*,#1423,.T.);
#1425=ORIENTED_EDGE('',*,*,#693,.T.);
#1426=EDGE_LOOP('',(#1356,#1417,#1424,#1425));
#1427=FACE_BOUND('',#1426,.T.);
#1428=ADVANCED_FACE('F590',(#1427),#1355,.T.);
#1429=CARTESIAN_POINT('',(120.86622545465,9.55000000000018,19.5618100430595));
#1430=DIRECTION('',(0.940144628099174,0.,-0.340775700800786));
#1431=DIRECTION('',(0.,1.,0.));
#1432=AXIS2_PLACEMENT_3D('',#1429,#1430,#1431);
#1433=CIRCLE('',#1432,1.59999999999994);
#1434=CARTESIAN_POINT('',(47.2434292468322,0.,-184.999446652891));
#1435=DIRECTION('',(0.,-1.,0.));
#1436=AXIS1_PLACEMENT('',#1434,#1435);
#1437=SURFACE_OF_REVOLUTION('',#1433,#1436);
#1438=ORIENTED_EDGE('',*,*,#1423,.F.);
#1439=CARTESIAN_POINT('',(98.3372747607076,9.87931034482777,27.9284725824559));
#1440=CARTESIAN_POINT('',(98.2900586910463,9.90242931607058,27.9348017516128));
#1441=CARTESIAN_POINT('',(98.242629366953,9.92523258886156,27.9406852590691));
#1442=CARTESIAN_POINT('',(98.1474081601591,9.97017379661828,27.9516104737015));
#1443=CARTESIAN_POINT('',(98.0996166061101,9.9923122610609,27.9566528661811));
#1444=CARTESIAN_POINT('',(98.0036756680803,10.0359195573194,27.9659537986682));
#1445=CARTESIAN_POINT('',(97.9555264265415,10.0573886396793,27.9702126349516));
#1446=CARTESIAN_POINT('',(97.8588764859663,10.0996523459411,27.9780006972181));
#1447=CARTESIAN_POINT('',(97.8103757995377,10.1204469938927,27.9815299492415));
#1448=CARTESIAN_POINT('',(97.7130222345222,10.1613597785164,27.9879114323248));
#1449=CARTESIAN_POINT('',(97.6641692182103,10.1814776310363,27.9907633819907));
#1450=CARTESIAN_POINT('',(97.5661121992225,10.2210336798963,27.9958404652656));
#1451=CARTESIAN_POINT('',(97.5169079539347,10.2404713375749,27.998065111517));
#1452=CARTESIAN_POINT('',(97.467556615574,10.2595562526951,28.));
#1453=B_SPLINE_CURVE_WITH_KNOTS('',3,(#1439,#1440,#1441,#1442,#1443,#1444,#1445,#1446,#1447,
#1448,#1449,#1450,#1451,#1452),.UNSPECIFIED.,.F.,.F.,(4,2,2,2,2,2,4),(0.,0.158851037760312,
0.317572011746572,0.476232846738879,0.634888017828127,0.793608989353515,0.952452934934),.UNSPECIFIED.);
#1454=CARTESIAN_POINT('',(97.4675566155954,10.2595562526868,28.));
#1455=VERTEX_POINT('',#1454);
#1456=EDGE_CURVE('E287',#1415,#1455,#1453,.T.);
#1457=ORIENTED_EDGE('',*,*,#1456,.T.);
#1458=CARTESIAN_POINT('',(98.0382672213,9.87931034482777,28.));
#1459=CARTESIAN_POINT('',(98.0260557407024,9.8927722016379,28.));
#1460=CARTESIAN_POINT('',(98.0134269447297,9.90584132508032,28.));
#1461=CARTESIAN_POINT('',(97.9874783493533,9.93125473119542,28.));
#1462=CARTESIAN_POINT('',(97.9741591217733,9.94359959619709,28.));
#1463=CARTESIAN_POINT('',(97.9335584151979,9.97948610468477,28.));
#1464=CARTESIAN_POINT('',(97.9054426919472,10.0020836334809,28.));
#1465=CARTESIAN_POINT('',(97.8477226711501,10.0451551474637,28.));
#1466=CARTESIAN_POINT('',(97.8181206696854,10.065632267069,28.));
#1467=CARTESIAN_POINT('',(97.7581981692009,10.1046062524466,28.));
#1468=CARTESIAN_POINT('',(97.727892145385,10.123125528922,28.));
#1469=CARTESIAN_POINT('',(97.6664120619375,10.1587811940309,28.));
#1470=CARTESIAN_POINT('',(97.6352365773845,10.1759151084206,28.));
#1471=CARTESIAN_POINT('',(97.572226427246,10.2089821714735,28.));
#1472=CARTESIAN_POINT('',(97.5403912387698,10.2249143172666,28.));
#1473=CARTESIAN_POINT('',(97.4336728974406,10.2761736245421,28.));
#1474=CARTESIAN_POINT('',(97.3576850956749,10.3092044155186,28.));
#1475=CARTESIAN_POINT('',(97.2040436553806,10.3710642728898,28.));
#1476=CARTESIAN_POINT('',(97.126389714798,10.3998925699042,28.));
#1477=CARTESIAN_POINT('',(96.9698712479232,10.4542650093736,28.));
#1478=CARTESIAN_POINT('',(96.891005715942,10.479806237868,28.));
#1479=CARTESIAN_POINT('',(96.7324458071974,10.5281938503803,28.));
#1480=CARTESIAN_POINT('',(96.6527512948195,10.5510397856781,28.));
#1481=CARTESIAN_POINT('',(96.4909598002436,10.594955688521,28.));
#1482=CARTESIAN_POINT('',(96.4088489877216,10.6159744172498,28.));
#1483=CARTESIAN_POINT('',(96.2442079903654,10.65597528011,28.));
#1484=CARTESIAN_POINT('',(96.1616782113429,10.6749590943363,28.));
#1485=CARTESIAN_POINT('',(95.996265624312,10.7111645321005,28.));
#1486=CARTESIAN_POINT('',(95.9133829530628,10.7283867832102,28.));
#1487=CARTESIAN_POINT('',(95.7473177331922,10.7612788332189,28.));
#1488=CARTESIAN_POINT('',(95.6641352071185,10.7769487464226,28.));
#1489=CARTESIAN_POINT('',(95.4931000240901,10.8076944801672,28.));
#1490=CARTESIAN_POINT('',(95.4052338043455,10.8226946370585,28.));
#1491=CARTESIAN_POINT('',(95.2292628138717,10.8513098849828,28.));
#1492=CARTESIAN_POINT('',(95.1411580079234,10.8649247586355,28.));
#1493=CARTESIAN_POINT('',(94.9647487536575,10.8908935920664,28.));
#1494=CARTESIAN_POINT('',(94.8764442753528,10.9032473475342,28.));
#1495=CARTESIAN_POINT('',(94.6996715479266,10.9267961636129,28.));
#1496=CARTESIAN_POINT('',(94.6112032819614,10.9379910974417,28.));
#1497=CARTESIAN_POINT('',(94.4376140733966,10.9588889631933,28.));
#1498=CARTESIAN_POINT('',(94.3524980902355,10.9686332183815,28.));
#1499=CARTESIAN_POINT('',(94.1821744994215,10.9871951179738,28.));
#1500=CARTESIAN_POINT('',(94.09696690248,10.9960128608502,28.));
#1501=CARTESIAN_POINT('',(93.926488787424,11.0127772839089,28.));
#1502=CARTESIAN_POINT('',(93.8412182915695,11.0207241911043,28.));
#1503=CARTESIAN_POINT('',(93.670641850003,11.0357935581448,28.));
#1504=CARTESIAN_POINT('',(93.5853359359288,11.0429163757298,28.));
#1505=CARTESIAN_POINT('',(93.5,11.0496525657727,28.));
#1506=B_SPLINE_CURVE_WITH_KNOTS('',3,(#1458,#1459,#1460,#1461,#1462,#1463,#1464,#1465,#1466,
#1467,#1468,#1469,#1470,#1471,#1472,#1473,#1474,#1475,#1476,#1477,#1478,#1479,#1480,#1481,#1482,
#1483,#1484,#1485,#1486,#1487,#1488,#1489,#1490,#1491,#1492,#1493,#1494,#1495,#1496,#1497,#1498,
#1499,#1500,#1501,#1502,#1503,#1504,#1505),.UNSPECIFIED.,.F.,.F.,(4,2,2,2,2,2,2,2,2,2,2,2,2,2,2,
2,2,2,2,2,2,2,2,4),(0.,0.0545008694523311,0.108957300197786,0.217035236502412,0.324951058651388,
0.431454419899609,0.538143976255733,0.644921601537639,0.893291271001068,1.14170635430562,
1.39034016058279,1.63901530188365,1.89326022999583,2.14729360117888,2.40123615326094,
2.65515999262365,2.92255979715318,3.19000149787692,3.45748645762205,3.72500065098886,
3.98201112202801,4.2389942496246,4.49591022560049,4.75271425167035),.UNSPECIFIED.);
#1507=CARTESIAN_POINT('',(96.0943064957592,10.6896947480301,28.));
#1508=VERTEX_POINT('',#1507);
#1509=EDGE_CURVE('E9',#1455,#1508,#1506,.T.);
#1510=ORIENTED_EDGE('',*,*,#1509,.T.);
#1511=CARTESIAN_POINT('',(96.0943064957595,10.68969474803,28.));
#1512=CARTESIAN_POINT('',(96.0245736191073,10.706618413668,27.99837551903));
#1513=CARTESIAN_POINT('',(95.9546771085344,10.7228591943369,27.9966632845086));
#1514=CARTESIAN_POINT('',(95.814673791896,10.753949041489,27.9932569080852));
#1515=CARTESIAN_POINT('',(95.7445673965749,10.76879995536,27.9915627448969));
#1516=CARTESIAN_POINT('',(95.604141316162,10.7971160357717,27.9883822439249));
#1517=CARTESIAN_POINT('',(95.5338219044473,10.8105825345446,27.9868957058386));
#1518=CARTESIAN_POINT('',(95.3929657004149,10.8361340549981,27.9843509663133));
#1519=CARTESIAN_POINT('',(95.3224290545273,10.8482198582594,27.9832925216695));
#1520=CARTESIAN_POINT('',(95.1811050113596,10.8710169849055,27.9818531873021));
#1521=CARTESIAN_POINT('',(95.110317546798,10.8817279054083,27.981472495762));
#1522=CARTESIAN_POINT('',(94.968523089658,10.9017690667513,27.9816751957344));
#1523=CARTESIAN_POINT('',(94.8975160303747,10.9110988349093,27.9822589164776));
#1524=CARTESIAN_POINT('',(94.755286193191,10.9283755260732,27.9847121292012));
#1525=CARTESIAN_POINT('',(94.6840632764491,10.9363211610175,27.9865828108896));
#1526=CARTESIAN_POINT('',(94.54141270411,10.9508270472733,27.9919674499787));
#1527=CARTESIAN_POINT('',(94.4699849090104,10.9573848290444,27.9954843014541));
#1528=CARTESIAN_POINT('',(94.3985532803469,10.963238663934,28.));
#1529=B_SPLINE_CURVE_WITH_KNOTS('',3,(#1511,#1512,#1513,#1514,#1515,#1516,#1517,#1518,#1519,
#1520,#1521,#1522,#1523,#1524,#1525,#1526,#1527,#1528),.UNSPECIFIED.,.F.,.F.,(4,2,2,2,2,2,2,2,
4),(0.,0.215323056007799,0.430355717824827,0.645179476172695,0.859881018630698,1.0746453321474,
1.28948297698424,1.50451949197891,1.71993548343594),.UNSPECIFIED.);
#1530=CARTESIAN_POINT('',(94.3985532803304,10.9632386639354,28.));
#1531=VERTEX_POINT('',#1530);
#1532=EDGE_CURVE('E280',#1508,#1531,#1529,.T.);
#1533=ORIENTED_EDGE('',*,*,#1532,.T.);
#1534=CARTESIAN_POINT('',(93.5,11.0496525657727,28.));
#1535=VERTEX_POINT('',#1534);
#1536=EDGE_CURVE('E20',#1531,#1535,#1506,.T.);
#1537=ORIENTED_EDGE('',*,*,#1536,.T.);
#1538=CARTESIAN_POINT('',(93.5,11.0496525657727,28.));
#1539=CARTESIAN_POINT('',(93.5,11.0579942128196,27.9770480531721));
#1540=CARTESIAN_POINT('',(93.5,11.0658293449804,27.9539115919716));
#1541=CARTESIAN_POINT('',(93.5,11.08044654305,27.9074052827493));
#1542=CARTESIAN_POINT('',(93.5,11.0872325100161,27.8840366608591));
#1543=CARTESIAN_POINT('',(93.5,11.0997631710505,27.8370707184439));
#1544=CARTESIAN_POINT('',(93.5,11.1055098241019,27.8134739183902));
#1545=CARTESIAN_POINT('',(93.5,11.1264600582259,27.7184865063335));
#1546=CARTESIAN_POINT('',(93.5,11.1375132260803,27.6461630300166));
#1547=CARTESIAN_POINT('',(93.5,11.1437941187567,27.5733366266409));
#1548=B_SPLINE_CURVE_WITH_KNOTS('',3,(#1538,#1539,#1540,#1541,#1542,#1543,#1544,#1545,#1546,
#1547),.UNSPECIFIED.,.F.,.F.,(4,2,2,2,4),(0.,0.0732573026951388,0.146235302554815,
0.219074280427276,0.4380082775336),.UNSPECIFIED.);
#1549=CARTESIAN_POINT('',(93.5,11.1437941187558,27.5733366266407));
#1550=VERTEX_POINT('',#1549);
#1551=EDGE_CURVE('E214',#1535,#1550,#1548,.T.);
#1552=ORIENTED_EDGE('',*,*,#1551,.T.);
#1553=CARTESIAN_POINT('',(47.2434292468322,11.1437941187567,-184.999446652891));
#1554=DIRECTION('',(0.,-1.,0.));
#1555=DIRECTION('',(1.,0.,0.));
#1556=AXIS2_PLACEMENT_3D('',#1553,#1554,#1555);
#1557=CIRCLE('',#1556,217.547370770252);
#1558=EDGE_CURVE('E347',#1550,#426,#1557,.T.);
#1559=ORIENTED_EDGE('',*,*,#1558,.T.);
#1560=ORIENTED_EDGE('',*,*,#562,.T.);
#1561=EDGE_LOOP('',(#1438,#1457,#1510,#1533,#1537,#1552,#1559,#1560));
#1562=FACE_BOUND('',#1561,.T.);
#1563=ADVANCED_FACE('F329',(#1562),#1437,.T.);
#1564=CARTESIAN_POINT('',(120.989848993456,8.47425322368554,19.9028672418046));
#1565=DIRECTION('',(0.940144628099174,0.,-0.340775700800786));
#1566=DIRECTION('',(0.,1.,0.));
#1567=AXIS2_PLACEMENT_3D('',#1564,#1565,#1566);
#1568=CIRCLE('',#1567,2.67875466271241);
#1569=CARTESIAN_POINT('',(47.2434292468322,0.,-184.999446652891));
#1570=DIRECTION('',(0.,-1.,0.));
#1571=AXIS1_PLACEMENT('',#1569,#1570);
#1572=SURFACE_OF_REVOLUTION('',#1568,#1571);
#1573=ORIENTED_EDGE('',*,*,#1558,.F.);
#1574=CARTESIAN_POINT('',(93.5,11.1437941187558,27.5733366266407));
#1575=CARTESIAN_POINT('',(93.5,11.1343057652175,27.4564772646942));
#1576=CARTESIAN_POINT('',(93.5,11.1174827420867,27.34034800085));
#1577=CARTESIAN_POINT('',(93.5,11.0854857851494,27.1876211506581));
#1578=CARTESIAN_POINT('',(93.5,11.0767014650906,27.1496593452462));
#1579=CARTESIAN_POINT('',(93.5,11.0575359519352,27.0740686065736));
#1580=CARTESIAN_POINT('',(93.5,11.0471519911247,27.0364403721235));
#1581=CARTESIAN_POINT('',(93.5,11.0247761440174,26.961521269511));
#1582=CARTESIAN_POINT('',(93.5,11.0127787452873,26.9242320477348));
#1583=CARTESIAN_POINT('',(93.5,11.0000000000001,26.8872131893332));
#1584=B_SPLINE_CURVE_WITH_KNOTS('',3,(#1574,#1575,#1576,#1577,#1578,#1579,#1580,#1581,#1582,
#1583),.UNSPECIFIED.,.F.,.F.,(4,2,2,2,4),(0.,0.351207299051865,0.468071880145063,
0.585140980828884,0.702620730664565),.UNSPECIFIED.);
#1585=CARTESIAN_POINT('',(93.5,11.,26.8872131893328));
#1586=VERTEX_POINT('',#1585);
#1587=EDGE_CURVE('E312',#1550,#1586,#1584,.T.);
#1588=ORIENTED_EDGE('',*,*,#1587,.T.);
#1589=CARTESIAN_POINT('',(93.5,11.,26.8872131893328));
#1590=CARTESIAN_POINT('',(93.5707909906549,11.0000010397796,26.8717864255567));
#1591=CARTESIAN_POINT('',(93.6411308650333,10.9993167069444,26.854385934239));
#1592=CARTESIAN_POINT('',(93.780472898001,10.9966431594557,26.8161161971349));
#1593=CARTESIAN_POINT('',(93.8494798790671,10.9946602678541,26.7952641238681));
#1594=CARTESIAN_POINT('',(93.9862502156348,10.9894602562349,26.7504645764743));
#1595=CARTESIAN_POINT('',(94.0540160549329,10.986245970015,26.7265242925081));
#1596=CARTESIAN_POINT('',(94.188436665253,10.9786421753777,26.6759910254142));
#1597=CARTESIAN_POINT('',(94.2550920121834,10.9742532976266,26.6493994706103));
#1598=CARTESIAN_POINT('',(94.3868092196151,10.964392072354,26.5942437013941));
#1599=CARTESIAN_POINT('',(94.4518799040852,10.9589294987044,26.5656986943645));
#1600=CARTESIAN_POINT('',(94.5811703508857,10.9469306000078,26.5068048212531));
#1601=CARTESIAN_POINT('',(94.6453892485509,10.9403932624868,26.4764542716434));
#1602=CARTESIAN_POINT('',(94.7730686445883,10.9262722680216,26.4142934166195));
#1603=CARTESIAN_POINT('',(94.8365284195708,10.9186876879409,26.3824818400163));
#1604=CARTESIAN_POINT('',(94.9627584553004,10.9024945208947,26.3176990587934));
#1605=CARTESIAN_POINT('',(95.0255283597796,10.8938854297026,26.2847272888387));
#1606=CARTESIAN_POINT('',(95.222996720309,10.8650777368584,26.1790708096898));
#1607=CARTESIAN_POINT('',(95.3565508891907,10.8430331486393,26.1047449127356));
#1608=CARTESIAN_POINT('',(95.6214664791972,10.7943275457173,25.9537877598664));
#1609=CARTESIAN_POINT('',(95.7528279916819,10.7676667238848,25.8771566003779));
#1610=CARTESIAN_POINT('',(96.0139052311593,10.7097226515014,25.7228198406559));
#1611=CARTESIAN_POINT('',(96.143620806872,10.6784389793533,25.6451141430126));
#1612=CARTESIAN_POINT('',(96.4017427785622,10.611205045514,25.4895610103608));
#1613=CARTESIAN_POINT('',(96.530149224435,10.5752549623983,25.4117135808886));
#1614=CARTESIAN_POINT('',(96.785871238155,10.4986123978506,25.2566196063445));
#1615=CARTESIAN_POINT('',(96.9131870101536,10.4579208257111,25.1793729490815));
#1616=CARTESIAN_POINT('',(97.1701193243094,10.3705880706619,25.0241594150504));
#1617=CARTESIAN_POINT('',(97.2997125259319,10.3238223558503,24.9462238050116));
#1618=CARTESIAN_POINT('',(97.5580300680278,10.225043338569,24.7922849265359));
#1619=CARTESIAN_POINT('',(97.6867544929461,10.1730305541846,24.7162814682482));
#1620=CARTESIAN_POINT('',(97.9434242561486,10.0635703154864,24.5668343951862));
#1621=CARTESIAN_POINT('',(98.0713694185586,10.0061216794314,24.4933913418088));
#1622=CARTESIAN_POINT('',(98.3265691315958,9.88555374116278,24.3497121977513));
#1623=CARTESIAN_POINT('',(98.453822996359,9.82242962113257,24.2794789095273));
#1624=CARTESIAN_POINT('',(98.707726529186,9.69020503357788,24.142969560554));
#1625=CARTESIAN_POINT('',(98.8343745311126,9.62109313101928,24.0767014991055));
#1626=CARTESIAN_POINT('',(98.9605693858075,9.54893617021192,24.0128972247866));
#1627=B_SPLINE_CURVE_WITH_KNOTS('',3,(#1589,#1590,#1591,#1592,#1593,#1594,#1595,#1596,#1597,
#1598,#1599,#1600,#1601,#1602,#1603,#1604,#1605,#1606,#1607,#1608,#1609,#1610,#1611,#1612,#1613,
#1614,#1615,#1616,#1617,#1618,#1619,#1620,#1621,#1622,#1623,#1624,#1625,#1626),.UNSPECIFIED.,
.F.,.F.,(4,2,2,2,2,2,2,2,2,2,2,2,2,2,2,2,2,2,4),(0.,0.217296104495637,0.433541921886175,
0.649293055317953,0.864928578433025,1.07868519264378,1.29264434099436,1.50679331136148,
1.72104811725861,2.18418173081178,2.6472959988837,3.11045252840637,3.57359133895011,
4.03664147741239,4.5114130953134,4.98613788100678,5.46096610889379,5.93620128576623,
6.41236492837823),.UNSPECIFIED.);
#1628=CARTESIAN_POINT('',(94.5949482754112,10.9453683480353,26.5));
#1629=VERTEX_POINT('',#1628);
#1630=EDGE_CURVE('E206',#1586,#1629,#1627,.T.);
#1631=ORIENTED_EDGE('',*,*,#1630,.T.);
#1632=CARTESIAN_POINT('',(98.1830267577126,11.1437941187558,26.5));
#1633=CARTESIAN_POINT('',(97.9586864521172,11.1394208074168,26.5));
#1634=CARTESIAN_POINT('',(97.7343764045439,11.1335242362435,26.5));
#1635=CARTESIAN_POINT('',(97.2859167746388,11.1187238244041,26.5));
#1636=CARTESIAN_POINT('',(97.0617671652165,11.1098208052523,26.5));
#1637=CARTESIAN_POINT('',(96.6136475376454,11.0890462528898,26.5));
#1638=CARTESIAN_POINT('',(96.3896774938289,11.0771752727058,26.5));
#1639=CARTESIAN_POINT('',(95.9419372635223,11.0504657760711,26.5));
#1640=CARTESIAN_POINT('',(95.7181670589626,11.0356275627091,26.5));
#1641=CARTESIAN_POINT('',(95.2721339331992,11.0030483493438,26.5));
#1642=CARTESIAN_POINT('',(95.0498697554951,10.9853245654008,26.5));
#1643=CARTESIAN_POINT('',(94.6055836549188,10.9468500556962,26.5));
#1644=CARTESIAN_POINT('',(94.3835617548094,10.9260990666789,26.5000000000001));
#1645=CARTESIAN_POINT('',(93.9397899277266,10.8814645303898,26.4999999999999));
#1646=CARTESIAN_POINT('',(93.7180400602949,10.85758038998,26.4999999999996));
#1647=CARTESIAN_POINT('',(93.2748469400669,10.8065229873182,26.5000000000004));
#1648=CARTESIAN_POINT('',(93.0534038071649,10.779348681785,26.5000000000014));
#1649=CARTESIAN_POINT('',(92.6105700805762,10.7214502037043,26.5000000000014));
#1650=CARTESIAN_POINT('',(92.3891803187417,10.6907196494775,26.5000000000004));
#1651=CARTESIAN_POINT('',(91.9469775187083,10.62545238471,26.4999999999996));
#1652=CARTESIAN_POINT('',(91.7261644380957,10.5909159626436,26.4999999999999));
#1653=CARTESIAN_POINT('',(91.285332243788,10.5176357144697,26.5000000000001));
#1654=CARTESIAN_POINT('',(91.065312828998,10.4788937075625,26.5));
#1655=CARTESIAN_POINT('',(90.6263100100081,10.396634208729,26.5));
#1656=CARTESIAN_POINT('',(90.4073260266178,10.3531198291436,26.5));
#1657=CARTESIAN_POINT('',(89.9692253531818,10.2601703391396,26.5));
#1658=CARTESIAN_POINT('',(89.7501158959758,10.2107009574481,26.5));
#1659=CARTESIAN_POINT('',(89.3135463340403,10.1047714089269,26.5));
#1660=CARTESIAN_POINT('',(89.0960863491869,10.0483107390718,26.5));
#1661=CARTESIAN_POINT('',(88.7716973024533,9.95675773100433,26.5));
#1662=CARTESIAN_POINT('',(88.6638050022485,9.92507578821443,26.5));
#1663=CARTESIAN_POINT('',(88.4488598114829,9.85902106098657,26.5));
#1664=CARTESIAN_POINT('',(88.3418068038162,9.82464865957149,26.5));
#1665=CARTESIAN_POINT('',(88.1283604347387,9.75252985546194,26.5));
#1666=CARTESIAN_POINT('',(88.0219713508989,9.71477065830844,26.5));
#1667=CARTESIAN_POINT('',(87.8635050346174,9.65508918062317,26.5));
#1668=CARTESIAN_POINT('',(87.810856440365,9.63468289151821,26.5));
#1669=CARTESIAN_POINT('',(87.706015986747,9.59271290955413,26.5));
#1670=CARTESIAN_POINT('',(87.6538241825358,9.57114907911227,26.5));
#1671=CARTESIAN_POINT('',(87.601904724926,9.54893617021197,26.5));
#1672=B_SPLINE_CURVE_WITH_KNOTS('',3,(#1632,#1633,#1634,#1635,#1636,#1637,#1638,#1639,#1640,
#1641,#1642,#1643,#1644,#1645,#1646,#1647,#1648,#1649,#1650,#1651,#1652,#1653,#1654,#1655,#1656,
#1657,#1658,#1659,#1660,#1661,#1662,#1663,#1664,#1665,#1666,#1667,#1668,#1669,#1670,#1671),
.UNSPECIFIED.,.F.,.F.,(4,2,2,2,2,2,2,2,2,2,2,2,2,2,2,2,2,2,2,4),(0.,0.673142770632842,
1.34610175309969,2.01893543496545,2.69170042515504,3.36058947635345,4.02953673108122,
4.69861080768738,5.36789759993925,6.03840461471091,6.70886084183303,7.3790281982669,
8.04876106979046,8.72255123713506,9.39638991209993,9.73370530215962,10.0709727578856,
10.4095727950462,10.5789554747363,10.7483583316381),.UNSPECIFIED.);
#1673=CARTESIAN_POINT('',(88.9053338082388,9.99445058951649,26.5));
#1674=VERTEX_POINT('',#1673);
#1675=EDGE_CURVE('E645',#1629,#1674,#1672,.T.);
#1676=ORIENTED_EDGE('',*,*,#1675,.T.);
#1677=CARTESIAN_POINT('',(88.9053338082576,9.99445058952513,26.5));
#1678=CARTESIAN_POINT('',(88.8562689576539,9.97189444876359,26.4938196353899));
#1679=CARTESIAN_POINT('',(88.8073475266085,9.94896650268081,26.4878544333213));
#1680=CARTESIAN_POINT('',(88.7098337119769,9.90238479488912,26.4763949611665));
#1681=CARTESIAN_POINT('',(88.6612411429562,9.87873149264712,26.4709004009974));
#1682=CARTESIAN_POINT('',(88.5643820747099,9.83069667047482,26.4604167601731));
#1683=CARTESIAN_POINT('',(88.516115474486,9.80631539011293,26.4554275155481));
#1684=CARTESIAN_POINT('',(88.4199044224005,9.75682097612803,26.4459897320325));
#1685=CARTESIAN_POINT('',(88.3719599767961,9.7317078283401,26.4415412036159));
#1686=CARTESIAN_POINT('',(88.2763932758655,9.6807471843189,26.4332214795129));
#1687=CARTESIAN_POINT('',(88.2287711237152,9.65489946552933,26.429350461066));
#1688=CARTESIAN_POINT('',(88.1338481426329,9.60246616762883,26.4222237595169));
#1689=CARTESIAN_POINT('',(88.0865475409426,9.57588012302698,26.4189684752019));
#1690=CARTESIAN_POINT('',(88.0394306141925,9.54893617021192,26.4160417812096));
#1691=B_SPLINE_CURVE_WITH_KNOTS('',3,(#1677,#1678,#1679,#1680,#1681,#1682,#1683,#1684,#1685,
#1686,#1687,#1688,#1689,#1690),.UNSPECIFIED.,.F.,.F.,(4,2,2,2,2,2,4),(0.,0.163060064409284,
0.32601889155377,0.488924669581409,0.651833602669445,0.814792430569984,0.977856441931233),.UNSPECIFIED.);
#1692=EDGE_CURVE('E668',#1674,#34,#1691,.T.);
#1693=ORIENTED_EDGE('',*,*,#1692,.T.);
#1694=ORIENTED_EDGE('',*,*,#37,.T.);
#1695=ORIENTED_EDGE('',*,*,#434,.T.);
#1696=EDGE_LOOP('',(#1573,#1588,#1631,#1676,#1693,#1694,#1695));
#1697=FACE_BOUND('',#1696,.T.);
#1698=ADVANCED_FACE('F323',(#1697),#1572,.T.);
#1699=CARTESIAN_POINT('',(93.5,0.,26.5));
#1700=DIRECTION('',(0.,0.,1.));
#1701=DIRECTION('',(0.,-1.,0.));
#1702=AXIS2_PLACEMENT_3D('',#1699,#1700,#1701);
#1703=PLANE('',#1702);
#1704=ORIENTED_EDGE('',*,*,#1121,.F.);
#1705=CARTESIAN_POINT('',(93.5,0.,26.5));
#1706=DIRECTION('',(0.,0.,-1.));
#1707=DIRECTION('',(0.,-1.,0.));
#1708=AXIS2_PLACEMENT_3D('',#1705,#1706,#1707);
#1709=CIRCLE('',#1708,11.);
#1710=EDGE_CURVE('E675',#1120,#1118,#1709,.T.);
#1711=ORIENTED_EDGE('',*,*,#1710,.F.);
#1712=EDGE_LOOP('',(#1704,#1711));
#1713=FACE_BOUND('',#1712,.T.);
#1714=ADVANCED_FACE('F328',(#1713),#1703,.T.);
#1715=ORIENTED_EDGE('',*,*,#1675,.F.);
#1716=EDGE_CURVE('E674',#1674,#1629,#1709,.T.);
#1717=ORIENTED_EDGE('',*,*,#1716,.F.);
#1718=EDGE_LOOP('',(#1715,#1717));
#1719=FACE_BOUND('',#1718,.T.);
#1720=ADVANCED_FACE('F654',(#1719),#1703,.T.);
#1721=CARTESIAN_POINT('',(93.5,0.,26.5));
#1722=DIRECTION('',(0.,0.,-1.));
#1723=DIRECTION('',(0.,1.,0.));
#1724=AXIS2_PLACEMENT_3D('',#1721,#1722,#1723);
#1725=CYLINDRICAL_SURFACE('',#1724,11.);
#1726=ORIENTED_EDGE('',*,*,#1716,.T.);
#1727=ORIENTED_EDGE('',*,*,#1630,.F.);
#1728=DIRECTION('',(0.,0.,-1.));
#1729=VECTOR('',#1728,1.);
#1730=CARTESIAN_POINT('',(93.5,11.,28.));
#1731=LINE('',#1730,#1729);
#1732=CARTESIAN_POINT('',(93.5,11.,28.));
#1733=VERTEX_POINT('',#1732);
#1734=EDGE_CURVE('E202',#1733,#1586,#1731,.T.);
#1735=ORIENTED_EDGE('',*,*,#1734,.F.);
#1736=CARTESIAN_POINT('',(93.5,0.,28.));
#1737=DIRECTION('',(0.,0.,1.));
#1738=DIRECTION('',(0.,-1.,0.));
#1739=AXIS2_PLACEMENT_3D('',#1736,#1737,#1738);
#1740=CIRCLE('',#1739,11.);
#1741=EDGE_CURVE('E190',#1531,#1733,#1740,.T.);
#1742=ORIENTED_EDGE('',*,*,#1741,.F.);
#1743=ORIENTED_EDGE('',*,*,#1532,.F.);
#1744=EDGE_CURVE('E198',#1455,#1508,#1740,.T.);
#1745=ORIENTED_EDGE('',*,*,#1744,.F.);
#1746=ORIENTED_EDGE('',*,*,#1456,.F.);
#1747=ORIENTED_EDGE('',*,*,#1416,.F.);
#1748=ORIENTED_EDGE('',*,*,#1334,.F.);
#1749=EDGE_CURVE('E224',#1310,#1314,#1740,.T.);
#1750=ORIENTED_EDGE('',*,*,#1749,.F.);
#1751=ORIENTED_EDGE('',*,*,#1311,.F.);
#1752=CARTESIAN_POINT('',(93.5,-11.,28.));
#1753=VERTEX_POINT('',#1752);
#1754=EDGE_CURVE('E200',#1753,#1287,#1740,.T.);
#1755=ORIENTED_EDGE('',*,*,#1754,.F.);
#1756=DIRECTION('',(0.,0.,-1.));
#1757=VECTOR('',#1756,1.);
#1758=CARTESIAN_POINT('',(93.5,-11.,28.));
#1759=LINE('',#1758,#1757);
#1760=EDGE_CURVE('E210',#1753,#1165,#1759,.T.);
#1761=ORIENTED_EDGE('',*,*,#1760,.T.);
#1762=ORIENTED_EDGE('',*,*,#1166,.F.);
#1763=ORIENTED_EDGE('',*,*,#1710,.T.);
#1764=ORIENTED_EDGE('',*,*,#1207,.F.);
#1765=ORIENTED_EDGE('',*,*,#96,.F.);
#1766=ORIENTED_EDGE('',*,*,#1692,.F.);
#1767=EDGE_LOOP('',(#1726,#1727,#1735,#1742,#1743,#1745,#1746,#1747,#1748,#1750,#1751,#1755,
#1761,#1762,#1763,#1764,#1765,#1766));
#1768=FACE_BOUND('',#1767,.T.);
#1769=CARTESIAN_POINT('',(93.5,0.,0.));
#1770=DIRECTION('',(0.,0.,-1.));
#1771=DIRECTION('',(0.,-1.,0.));
#1772=AXIS2_PLACEMENT_3D('',#1769,#1770,#1771);
#1773=CIRCLE('',#1772,11.);
#1774=CARTESIAN_POINT('',(93.5,-11.,0.));
#1775=VERTEX_POINT('',#1774);
#1776=EDGE_CURVE('E677',#1775,#1775,#1773,.T.);
#1777=ORIENTED_EDGE('',*,*,#1776,.F.);
#1778=EDGE_LOOP('',(#1777));
#1779=FACE_BOUND('',#1778,.T.);
#1780=ADVANCED_FACE('F203',(#1768,#1779),#1725,.T.);
#1781=CARTESIAN_POINT('',(93.5,0.,0.));
#1782=DIRECTION('',(0.,0.,1.));
#1783=DIRECTION('',(0.,-1.,0.));
#1784=AXIS2_PLACEMENT_3D('',#1781,#1782,#1783);
#1785=PLANE('',#1784);
#1786=CARTESIAN_POINT('',(93.5,0.,0.));
#1787=DIRECTION('',(0.,0.,-1.));
#1788=DIRECTION('',(0.,-1.,0.));
#1789=AXIS2_PLACEMENT_3D('',#1786,#1787,#1788);
#1790=CIRCLE('',#1789,3.);
#1791=CARTESIAN_POINT('',(93.5,-3.,0.));
#1792=VERTEX_POINT('',#1791);
#1793=EDGE_CURVE('E218',#1792,#1792,#1790,.T.);
#1794=ORIENTED_EDGE('',*,*,#1793,.F.);
#1795=EDGE_LOOP('',(#1794));
#1796=FACE_BOUND('',#1795,.T.);
#1797=ORIENTED_EDGE('',*,*,#1776,.T.);
#1798=EDGE_LOOP('',(#1797));
#1799=FACE_BOUND('',#1798,.T.);
#1800=ADVANCED_FACE('F653',(#1796,#1799),#1785,.F.);
#1801=CARTESIAN_POINT('',(93.5,0.,28.));
#1802=DIRECTION('',(0.,0.,1.));
#1803=DIRECTION('',(0.,-1.,0.));
#1804=AXIS2_PLACEMENT_3D('',#1801,#1802,#1803);
#1805=PLANE('',#1804);
#1806=DIRECTION('',(0.,1.,0.));
#1807=VECTOR('',#1806,1.);
#1808=CARTESIAN_POINT('',(93.5,-11.,28.));
#1809=LINE('',#1808,#1807);
#1810=EDGE_CURVE('E223',#1234,#1753,#1809,.T.);
#1811=ORIENTED_EDGE('',*,*,#1810,.T.);
#1812=ORIENTED_EDGE('',*,*,#1754,.T.);
#1813=ORIENTED_EDGE('',*,*,#1288,.F.);
#1814=EDGE_LOOP('',(#1811,#1812,#1813));
#1815=FACE_BOUND('',#1814,.T.);
#1816=ADVANCED_FACE('F254',(#1815),#1805,.F.);
#1817=ORIENTED_EDGE('',*,*,#1749,.T.);
#1818=ORIENTED_EDGE('',*,*,#1315,.F.);
#1819=EDGE_LOOP('',(#1817,#1818));
#1820=FACE_BOUND('',#1819,.T.);
#1821=ADVANCED_FACE('F930',(#1820),#1805,.F.);
#1822=ORIENTED_EDGE('',*,*,#1744,.T.);
#1823=ORIENTED_EDGE('',*,*,#1509,.F.);
#1824=EDGE_LOOP('',(#1822,#1823));
#1825=FACE_BOUND('',#1824,.T.);
#1826=ADVANCED_FACE('F939',(#1825),#1805,.F.);
#1827=ORIENTED_EDGE('',*,*,#1741,.T.);
#1828=DIRECTION('',(0.,1.,0.));
#1829=VECTOR('',#1828,1.);
#1830=CARTESIAN_POINT('',(93.5,11.,28.));
#1831=LINE('',#1830,#1829);
#1832=EDGE_CURVE('E194',#1733,#1535,#1831,.T.);
#1833=ORIENTED_EDGE('',*,*,#1832,.T.);
#1834=ORIENTED_EDGE('',*,*,#1536,.F.);
#1835=EDGE_LOOP('',(#1827,#1833,#1834));
#1836=FACE_BOUND('',#1835,.T.);
#1837=ADVANCED_FACE('F192',(#1836),#1805,.F.);
#1838=CARTESIAN_POINT('',(93.5,11.,28.));
#1839=DIRECTION('',(-1.,0.,0.));
#1840=DIRECTION('',(0.,-1.,0.));
#1841=AXIS2_PLACEMENT_3D('',#1838,#1839,#1840);
#1842=PLANE('',#1841);
#1843=ORIENTED_EDGE('',*,*,#1832,.F.);
#1844=ORIENTED_EDGE('',*,*,#1734,.T.);
#1845=ORIENTED_EDGE('',*,*,#1587,.F.);
#1846=ORIENTED_EDGE('',*,*,#1551,.F.);
#1847=EDGE_LOOP('',(#1843,#1844,#1845,#1846));
#1848=FACE_BOUND('',#1847,.T.);
#1849=ADVANCED_FACE('F212',(#1848),#1842,.F.);
#1850=CARTESIAN_POINT('',(93.5,-11.,28.));
#1851=DIRECTION('',(-1.,0.,0.));
#1852=DIRECTION('',(0.,-1.,0.));
#1853=AXIS2_PLACEMENT_3D('',#1850,#1851,#1852);
#1854=PLANE('',#1853);
#1855=ORIENTED_EDGE('',*,*,#1760,.F.);
#1856=ORIENTED_EDGE('',*,*,#1810,.F.);
#1857=ORIENTED_EDGE('',*,*,#1235,.F.);
#1858=ORIENTED_EDGE('',*,*,#1181,.F.);
#1859=EDGE_LOOP('',(#1855,#1856,#1857,#1858));
#1860=FACE_BOUND('',#1859,.T.);
#1861=ADVANCED_FACE('F248',(#1860),#1854,.F.);
#1862=CARTESIAN_POINT('',(93.5,0.,12.));
#1863=DIRECTION('',(0.,0.,-1.));
#1864=DIRECTION('',(0.,1.,0.));
#1865=AXIS2_PLACEMENT_3D('',#1862,#1863,#1864);
#1866=CYLINDRICAL_SURFACE('',#1865,3.);
#1867=CARTESIAN_POINT('',(93.5,0.,12.));
#1868=DIRECTION('',(0.,0.,-1.));
#1869=DIRECTION('',(0.,-1.,0.));
#1870=AXIS2_PLACEMENT_3D('',#1867,#1868,#1869);
#1871=CIRCLE('',#1870,3.);
#1872=CARTESIAN_POINT('',(93.5,-3.,12.));
#1873=VERTEX_POINT('',#1872);
#1874=EDGE_CURVE('E215',#1873,#1873,#1871,.T.);
#1875=ORIENTED_EDGE('',*,*,#1874,.F.);
#1876=EDGE_LOOP('',(#1875));
#1877=FACE_BOUND('',#1876,.T.);
#1878=ORIENTED_EDGE('',*,*,#1793,.T.);
#1879=EDGE_LOOP('',(#1878));
#1880=FACE_BOUND('',#1879,.T.);
#1881=ADVANCED_FACE('F252',(#1877,#1880),#1866,.F.);
#1882=CARTESIAN_POINT('',(93.5,0.,12.));
#1883=DIRECTION('',(0.,0.,1.));
#1884=DIRECTION('',(0.,-1.,0.));
#1885=AXIS2_PLACEMENT_3D('',#1882,#1883,#1884);
#1886=PLANE('',#1885);
#1887=ORIENTED_EDGE('',*,*,#1874,.T.);
#1888=EDGE_LOOP('',(#1887));
#1889=FACE_BOUND('',#1888,.T.);
#1890=ADVANCED_FACE('F971',(#1889),#1886,.F.);
#1891=CLOSED_SHELL('',(#116,#144,#303,#464,#607,#697,#830,#902,#918,#971,#976,#986,#997,#1008,
#1020,#1032,#1037,#1057,#1066,#1211,#1346,#1428,#1563,#1698,#1714,#1720,#1780,#1800,#1816,#1821,
#1826,#1837,#1849,#1861,#1881,#1890));
#1892=MANIFOLD_SOLID_BREP('B1',#1891);
#1893=ADVANCED_BREP_SHAPE_REPRESENTATION('',(#18,#1892),#14);
#1894=SHAPE_DEFINITION_REPRESENTATION(#9,#1893);
ENDSEC;
END-ISO-10303-21;
